###############################################################
#  Generated by:      Cadence Innovus 23.12-s091_1
#  OS:                Linux x86_64(Host ID ecelinux-10.ece.cornell.edu)
#  Generated on:      Mon Oct 19 13:02:27 2026
#  Design:            mult
#  Command:           write_lef_abstract ./output/mult.0.8.lef -stripePin -cutObsMinSpacing -PGpinLayers {1 2 3 4 5 6 7 8 9} -specifyTopLayer 7
###############################################################

VERSION 5.8 ;

BUSBITCHARS "[]" ;
DIVIDERCHAR "/" ;

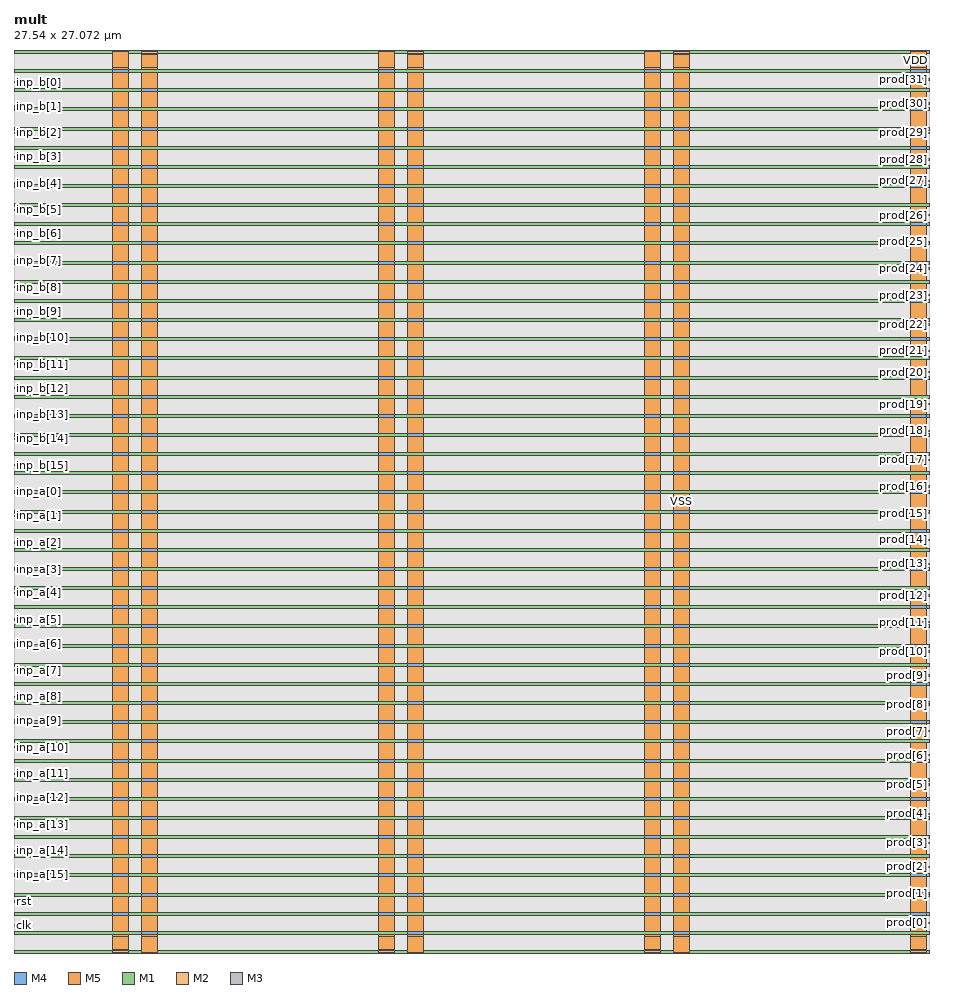
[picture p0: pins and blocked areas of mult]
MACRO mult
  CLASS BLOCK ;
  SIZE 27.540000 BY 27.072000 ;
  FOREIGN mult 0.000000 0.000000 ;
  ORIGIN 0 0 ;
  SYMMETRY X Y R90 ;
  PIN inp_a[15]
    DIRECTION INPUT ;
    USE SIGNAL ;
    ANTENNAPARTIALMETALAREA 0.0134 LAYER M4  ;
    ANTENNAPARTIALMETALSIDEAREA 0.000335 LAYER M4  ;
    ANTENNAPARTIALCUTAREA 0.0016 LAYER VIA4  ;
    ANTENNAPARTIALMETALAREA 0.5392 LAYER M5  ;
    ANTENNAPARTIALMETALSIDEAREA 0.01356 LAYER M5  ;
    ANTENNAMODEL OXIDE1 ;
    ANTENNAGATEAREA 0.007 LAYER M5  ;
    ANTENNAMAXAREACAR 150.658 LAYER M5  ;
    ANTENNAMAXSIDEAREACAR 4.14217 LAYER M5  ;
    ANTENNAMAXCUTCAR 4.32457 LAYER VIA5  ;
    PORT
      LAYER M4 ;
        RECT 0.000000 2.300000 0.375000 2.340000 ;
    END
  END inp_a[15]
  PIN inp_a[14]
    DIRECTION INPUT ;
    USE SIGNAL ;
    ANTENNAPARTIALMETALAREA 0.1702 LAYER M4  ;
    ANTENNAPARTIALMETALSIDEAREA 0.004255 LAYER M4  ;
    ANTENNAPARTIALCUTAREA 0.0016 LAYER VIA4  ;
    ANTENNAPARTIALMETALAREA 0.4824 LAYER M5  ;
    ANTENNAPARTIALMETALSIDEAREA 0.0121 LAYER M5  ;
    ANTENNAMODEL OXIDE1 ;
    ANTENNAGATEAREA 0.002 LAYER M5  ;
    ANTENNAMAXAREACAR 296.762 LAYER M5  ;
    ANTENNAMAXSIDEAREACAR 7.839 LAYER M5  ;
    ANTENNAMAXCUTCAR 3.872 LAYER VIA5  ;
    PORT
      LAYER M4 ;
        RECT 0.000000 3.020000 0.375000 3.060000 ;
    END
  END inp_a[14]
  PIN inp_a[13]
    DIRECTION INPUT ;
    USE SIGNAL ;
    ANTENNAPARTIALMETALAREA 0.0942 LAYER M4  ;
    ANTENNAPARTIALMETALSIDEAREA 0.002395 LAYER M4  ;
    ANTENNAMODEL OXIDE1 ;
    ANTENNAGATEAREA 0.008 LAYER M4  ;
    ANTENNAMAXAREACAR 109.725 LAYER M4  ;
    ANTENNAMAXSIDEAREACAR 3.3195 LAYER M4  ;
    ANTENNAMAXCUTCAR 4.224 LAYER VIA4  ;
    PORT
      LAYER M4 ;
        RECT 0.000000 3.820000 0.375000 3.860000 ;
    END
  END inp_a[13]
  PIN inp_a[12]
    DIRECTION INPUT ;
    USE SIGNAL ;
    ANTENNAMODEL OXIDE1 ;
    ANTENNAGATEAREA 0.002 LAYER M4  ;
    ANTENNAMAXAREACAR 88.106 LAYER M4  ;
    ANTENNAMAXSIDEAREACAR 2.8045 LAYER M4  ;
    ANTENNAMAXCUTCAR 2.048 LAYER VIA4  ;
    PORT
      LAYER M4 ;
        RECT 0.000000 4.620000 0.375000 4.660000 ;
    END
  END inp_a[12]
  PIN inp_a[11]
    DIRECTION INPUT ;
    USE SIGNAL ;
    ANTENNAPARTIALMETALAREA 0.07884 LAYER M4  ;
    ANTENNAPARTIALMETALSIDEAREA 0.002011 LAYER M4  ;
    ANTENNAMODEL OXIDE1 ;
    ANTENNAGATEAREA 0.008 LAYER M4  ;
    ANTENNAMAXAREACAR 108.321 LAYER M4  ;
    ANTENNAMAXSIDEAREACAR 3.28763 LAYER M4  ;
    ANTENNAMAXCUTCAR 4.224 LAYER VIA4  ;
    PORT
      LAYER M4 ;
        RECT 0.000000 5.340000 0.375000 5.380000 ;
    END
  END inp_a[11]
  PIN inp_a[10]
    DIRECTION INPUT ;
    USE SIGNAL ;
    ANTENNAMODEL OXIDE1 ;
    ANTENNAGATEAREA 0.002 LAYER M4  ;
    ANTENNAMAXAREACAR 158.442 LAYER M4  ;
    ANTENNAMAXSIDEAREACAR 5.0345 LAYER M4  ;
    ANTENNAMAXCUTCAR 3.584 LAYER VIA4  ;
    PORT
      LAYER M4 ;
        RECT 0.000000 6.140000 0.375000 6.180000 ;
    END
  END inp_a[10]
  PIN inp_a[9]
    DIRECTION INPUT ;
    USE SIGNAL ;
    ANTENNAPARTIALMETALAREA 0.04044 LAYER M4  ;
    ANTENNAPARTIALMETALSIDEAREA 0.001051 LAYER M4  ;
    ANTENNAMODEL OXIDE1 ;
    ANTENNAGATEAREA 0.002 LAYER M4  ;
    ANTENNAMAXAREACAR 64.502 LAYER M4  ;
    ANTENNAMAXSIDEAREACAR 1.8765 LAYER M4  ;
    ANTENNAMAXCUTCAR 3.584 LAYER VIA4  ;
    PORT
      LAYER M4 ;
        RECT 0.000000 6.940000 0.375000 6.980000 ;
    END
  END inp_a[9]
  PIN inp_a[8]
    DIRECTION INPUT ;
    USE SIGNAL ;
    ANTENNAPARTIALMETALAREA 0.2374 LAYER M4  ;
    ANTENNAPARTIALMETALSIDEAREA 0.005935 LAYER M4  ;
    ANTENNAPARTIALCUTAREA 0.0016 LAYER VIA4  ;
    ANTENNAPARTIALMETALAREA 0.1528 LAYER M5  ;
    ANTENNAPARTIALMETALSIDEAREA 0.00386 LAYER M5  ;
    ANTENNAMODEL OXIDE1 ;
    ANTENNAGATEAREA 0.002 LAYER M5  ;
    ANTENNAMAXAREACAR 173.886 LAYER M5  ;
    ANTENNAMAXSIDEAREACAR 4.9725 LAYER M5  ;
    ANTENNAMAXCUTCAR 3.36 LAYER VIA5  ;
    PORT
      LAYER M4 ;
        RECT 0.000000 7.660000 0.375000 7.700000 ;
    END
  END inp_a[8]
  PIN inp_a[7]
    DIRECTION INPUT ;
    USE SIGNAL ;
    ANTENNAPARTIALMETALAREA 0.129 LAYER M4  ;
    ANTENNAPARTIALMETALSIDEAREA 0.003305 LAYER M4  ;
    ANTENNAMODEL OXIDE1 ;
    ANTENNAGATEAREA 0.006 LAYER M4  ;
    ANTENNAMAXAREACAR 199.913 LAYER M4  ;
    ANTENNAMAXSIDEAREACAR 6.09663 LAYER M4  ;
    ANTENNAMAXCUTCAR 5.12 LAYER VIA4  ;
    PORT
      LAYER M4 ;
        RECT 0.000000 8.460000 0.375000 8.500000 ;
    END
  END inp_a[7]
  PIN inp_a[6]
    DIRECTION INPUT ;
    USE SIGNAL ;
    ANTENNAPARTIALMETALAREA 0.04336 LAYER M4  ;
    ANTENNAPARTIALMETALSIDEAREA 0.001084 LAYER M4  ;
    ANTENNAMODEL OXIDE1 ;
    ANTENNAGATEAREA 0.002 LAYER M4  ;
    ANTENNAMAXAREACAR 65.226 LAYER M4  ;
    ANTENNAMAXSIDEAREACAR 1.97 LAYER M4  ;
    ANTENNAMAXCUTCAR 2.56 LAYER VIA4  ;
    PORT
      LAYER M4 ;
        RECT 0.000000 9.260000 0.375000 9.300000 ;
    END
  END inp_a[6]
  PIN inp_a[5]
    DIRECTION INPUT ;
    USE SIGNAL ;
    ANTENNAPARTIALMETALAREA 0.04044 LAYER M4  ;
    ANTENNAPARTIALMETALSIDEAREA 0.001051 LAYER M4  ;
    ANTENNAMODEL OXIDE1 ;
    ANTENNAGATEAREA 0.003 LAYER M4  ;
    ANTENNAMAXAREACAR 65.8847 LAYER M4  ;
    ANTENNAMAXSIDEAREACAR 1.93383 LAYER M4  ;
    ANTENNAMAXCUTCAR 3.41333 LAYER VIA4  ;
    PORT
      LAYER M4 ;
        RECT 0.000000 9.980000 0.375000 10.020000 ;
    END
  END inp_a[5]
  PIN inp_a[4]
    DIRECTION INPUT ;
    USE SIGNAL ;
    ANTENNAPARTIALMETALAREA 0.04336 LAYER M4  ;
    ANTENNAPARTIALMETALSIDEAREA 0.001084 LAYER M4  ;
    ANTENNAMODEL OXIDE1 ;
    ANTENNAGATEAREA 0.002 LAYER M4  ;
    ANTENNAMAXAREACAR 65.226 LAYER M4  ;
    ANTENNAMAXSIDEAREACAR 1.97 LAYER M4  ;
    ANTENNAMAXCUTCAR 2.56 LAYER VIA4  ;
    PORT
      LAYER M4 ;
        RECT 0.000000 10.780000 0.375000 10.820000 ;
    END
  END inp_a[4]
  PIN inp_a[3]
    DIRECTION INPUT ;
    USE SIGNAL ;
    ANTENNAPARTIALMETALAREA 0.408 LAYER M4  ;
    ANTENNAPARTIALMETALSIDEAREA 0.01036 LAYER M4  ;
    ANTENNAMODEL OXIDE1 ;
    ANTENNAGATEAREA 0.003 LAYER M4  ;
    ANTENNAMAXAREACAR 210.362 LAYER M4  ;
    ANTENNAMAXSIDEAREACAR 5.79233 LAYER M4  ;
    ANTENNAPARTIALCUTAREA 0.0016 LAYER VIA4  ;
    ANTENNAMAXCUTCAR 6.67733 LAYER VIA4  ;
    ANTENNAPARTIALMETALAREA 0.0888 LAYER M5  ;
    ANTENNAPARTIALMETALSIDEAREA 0.00226 LAYER M5  ;
    ANTENNAGATEAREA 0.008 LAYER M5  ;
    ANTENNAMAXAREACAR 221.462 LAYER M5  ;
    ANTENNAMAXSIDEAREACAR 6.07483 LAYER M5  ;
    ANTENNAMAXCUTCAR 6.67733 LAYER VIA5  ;
    PORT
      LAYER M4 ;
        RECT 0.000000 11.500000 0.375000 11.540000 ;
    END
  END inp_a[3]
  PIN inp_a[2]
    DIRECTION INPUT ;
    USE SIGNAL ;
    ANTENNAPARTIALMETALAREA 0.13552 LAYER M4  ;
    ANTENNAPARTIALMETALSIDEAREA 0.003388 LAYER M4  ;
    ANTENNAMODEL OXIDE1 ;
    ANTENNAGATEAREA 0.002 LAYER M4  ;
    ANTENNAMAXAREACAR 124.314 LAYER M4  ;
    ANTENNAMAXSIDEAREACAR 3.5285 LAYER M4  ;
    ANTENNAMAXCUTCAR 2.56 LAYER VIA4  ;
    PORT
      LAYER M4 ;
        RECT 0.000000 12.300000 0.375000 12.340000 ;
    END
  END inp_a[2]
  PIN inp_a[1]
    DIRECTION INPUT ;
    USE SIGNAL ;
    ANTENNAPARTIALMETALAREA 0.21732 LAYER M4  ;
    ANTENNAPARTIALMETALSIDEAREA 0.005433 LAYER M4  ;
    ANTENNAMODEL OXIDE1 ;
    ANTENNAGATEAREA 0.007 LAYER M4  ;
    ANTENNAMAXAREACAR 113.696 LAYER M4  ;
    ANTENNAMAXSIDEAREACAR 3.32614 LAYER M4  ;
    ANTENNAMAXCUTCAR 4.43733 LAYER VIA4  ;
    PORT
      LAYER M4 ;
        RECT 0.000000 13.100000 0.375000 13.140000 ;
    END
  END inp_a[1]
  PIN inp_a[0]
    DIRECTION INPUT ;
    USE SIGNAL ;
    ANTENNAMODEL OXIDE1 ;
    ANTENNAGATEAREA 0.001 LAYER M4  ;
    ANTENNAMAXAREACAR 70.952 LAYER M4  ;
    ANTENNAMAXSIDEAREACAR 2.21 LAYER M4  ;
    ANTENNAMAXCUTCAR 3.072 LAYER VIA4  ;
    PORT
      LAYER M4 ;
        RECT 0.000000 13.820000 0.375000 13.860000 ;
    END
  END inp_a[0]
  PIN inp_b[15]
    DIRECTION INPUT ;
    USE SIGNAL ;
    ANTENNAPARTIALMETALAREA 0.59272 LAYER M4  ;
    ANTENNAPARTIALMETALSIDEAREA 0.014858 LAYER M4  ;
    ANTENNAMODEL OXIDE1 ;
    ANTENNAGATEAREA 0.005 LAYER M4  ;
    ANTENNAMAXAREACAR 309.418 LAYER M4  ;
    ANTENNAMAXSIDEAREACAR 8.9876 LAYER M4  ;
    ANTENNAPARTIALCUTAREA 0.0016 LAYER VIA4  ;
    ANTENNAMAXCUTCAR 3.392 LAYER VIA4  ;
    ANTENNAPARTIALMETALAREA 0.3504 LAYER M5  ;
    ANTENNAPARTIALMETALSIDEAREA 0.00884 LAYER M5  ;
    ANTENNAGATEAREA 0.009 LAYER M5  ;
    ANTENNAMAXAREACAR 348.351 LAYER M5  ;
    ANTENNAMAXSIDEAREACAR 9.96982 LAYER M5  ;
    ANTENNAMAXCUTCAR 5.92 LAYER VIA5  ;
    PORT
      LAYER M4 ;
        RECT 0.000000 14.620000 0.375000 14.660000 ;
    END
  END inp_b[15]
  PIN inp_b[14]
    DIRECTION INPUT ;
    USE SIGNAL ;
    ANTENNAPARTIALMETALAREA 0.55328 LAYER M4  ;
    ANTENNAPARTIALMETALSIDEAREA 0.013752 LAYER M4  ;
    ANTENNAMODEL OXIDE1 ;
    ANTENNAGATEAREA 0.009 LAYER M4  ;
    ANTENNAMAXAREACAR 257.342 LAYER M4  ;
    ANTENNAMAXSIDEAREACAR 7.732 LAYER M4  ;
    ANTENNAMAXCUTCAR 5.12 LAYER VIA4  ;
    PORT
      LAYER M4 ;
        RECT 0.000000 15.420000 0.375000 15.460000 ;
    END
  END inp_b[14]
  PIN inp_b[13]
    DIRECTION INPUT ;
    USE SIGNAL ;
    ANTENNAPARTIALMETALAREA 0.0838 LAYER M4  ;
    ANTENNAPARTIALMETALSIDEAREA 0.002095 LAYER M4  ;
    ANTENNAPARTIALCUTAREA 0.0016 LAYER VIA4  ;
    ANTENNAPARTIALMETALAREA 0.3576 LAYER M5  ;
    ANTENNAPARTIALMETALSIDEAREA 0.00898 LAYER M5  ;
    ANTENNAMODEL OXIDE1 ;
    ANTENNAGATEAREA 0.009 LAYER M5  ;
    ANTENNAMAXAREACAR 347.721 LAYER M5  ;
    ANTENNAMAXSIDEAREACAR 10.034 LAYER M5  ;
    ANTENNAMAXCUTCAR 5.44 LAYER VIA5  ;
    PORT
      LAYER M4 ;
        RECT 0.000000 16.140000 0.375000 16.180000 ;
    END
  END inp_b[13]
  PIN inp_b[12]
    DIRECTION INPUT ;
    USE SIGNAL ;
    ANTENNAPARTIALMETALAREA 0.76368 LAYER M4  ;
    ANTENNAPARTIALMETALSIDEAREA 0.019252 LAYER M4  ;
    ANTENNAMODEL OXIDE1 ;
    ANTENNAGATEAREA 0.006 LAYER M4  ;
    ANTENNAMAXAREACAR 241.898 LAYER M4  ;
    ANTENNAMAXSIDEAREACAR 6.87367 LAYER M4  ;
    ANTENNAPARTIALCUTAREA 0.0016 LAYER VIA4  ;
    ANTENNAMAXCUTCAR 5.38667 LAYER VIA4  ;
    ANTENNAPARTIALMETALAREA 0.252 LAYER M5  ;
    ANTENNAPARTIALMETALSIDEAREA 0.00634 LAYER M5  ;
    ANTENNAGATEAREA 0.009 LAYER M5  ;
    ANTENNAMAXAREACAR 269.898 LAYER M5  ;
    ANTENNAMAXSIDEAREACAR 7.57811 LAYER M5  ;
    ANTENNAMAXCUTCAR 5.38667 LAYER VIA5  ;
    PORT
      LAYER M4 ;
        RECT 0.000000 16.940000 0.375000 16.980000 ;
    END
  END inp_b[12]
  PIN inp_b[11]
    DIRECTION INPUT ;
    USE SIGNAL ;
    ANTENNAPARTIALMETALAREA 0.231 LAYER M4  ;
    ANTENNAPARTIALMETALSIDEAREA 0.005695 LAYER M4  ;
    ANTENNAMODEL OXIDE1 ;
    ANTENNAGATEAREA 0.001 LAYER M4  ;
    ANTENNAMAXAREACAR 309.778 LAYER M4  ;
    ANTENNAMAXSIDEAREACAR 8.24 LAYER M4  ;
    ANTENNAPARTIALCUTAREA 0.0032 LAYER VIA4  ;
    ANTENNAMAXCUTCAR 6.272 LAYER VIA4  ;
    ANTENNAPARTIALMETALAREA 0.484 LAYER M5  ;
    ANTENNAPARTIALMETALSIDEAREA 0.01222 LAYER M5  ;
    ANTENNAGATEAREA 0.009 LAYER M5  ;
    ANTENNAMAXAREACAR 363.556 LAYER M5  ;
    ANTENNAMAXSIDEAREACAR 9.59778 LAYER M5  ;
    ANTENNAMAXCUTCAR 6.272 LAYER VIA5  ;
    PORT
      LAYER M4 ;
        RECT 0.000000 17.660000 0.375000 17.700000 ;
    END
  END inp_b[11]
  PIN inp_b[10]
    DIRECTION INPUT ;
    USE SIGNAL ;
    ANTENNAPARTIALMETALAREA 0.37392 LAYER M4  ;
    ANTENNAPARTIALMETALSIDEAREA 0.009468 LAYER M4  ;
    ANTENNAMODEL OXIDE1 ;
    ANTENNAGATEAREA 0.006 LAYER M4  ;
    ANTENNAMAXAREACAR 272.842 LAYER M4  ;
    ANTENNAMAXSIDEAREACAR 8.24 LAYER M4  ;
    ANTENNAPARTIALCUTAREA 0.0032 LAYER VIA4  ;
    ANTENNAMAXCUTCAR 5.65333 LAYER VIA4  ;
    ANTENNAPARTIALMETALAREA 0.2736 LAYER M5  ;
    ANTENNAPARTIALMETALSIDEAREA 0.00692 LAYER M5  ;
    ANTENNAGATEAREA 0.009 LAYER M5  ;
    ANTENNAMAXAREACAR 303.242 LAYER M5  ;
    ANTENNAMAXSIDEAREACAR 9.00889 LAYER M5  ;
    ANTENNAMAXCUTCAR 5.65333 LAYER VIA5  ;
    PORT
      LAYER M4 ;
        RECT 0.000000 18.460000 0.375000 18.500000 ;
    END
  END inp_b[10]
  PIN inp_b[9]
    DIRECTION INPUT ;
    USE SIGNAL ;
    ANTENNAPARTIALMETALAREA 0.27936 LAYER M4  ;
    ANTENNAPARTIALMETALSIDEAREA 0.007064 LAYER M4  ;
    ANTENNAMODEL OXIDE1 ;
    ANTENNAGATEAREA 0.006 LAYER M4  ;
    ANTENNAMAXAREACAR 229.775 LAYER M4  ;
    ANTENNAMAXSIDEAREACAR 6.97533 LAYER M4  ;
    ANTENNAPARTIALCUTAREA 0.0016 LAYER VIA4  ;
    ANTENNAMAXCUTCAR 5.38667 LAYER VIA4  ;
    ANTENNAPARTIALMETALAREA 0.4536 LAYER M5  ;
    ANTENNAPARTIALMETALSIDEAREA 0.01138 LAYER M5  ;
    ANTENNAGATEAREA 0.009 LAYER M5  ;
    ANTENNAMAXAREACAR 280.175 LAYER M5  ;
    ANTENNAMAXSIDEAREACAR 8.23978 LAYER M5  ;
    ANTENNAMAXCUTCAR 5.38667 LAYER VIA5  ;
    PORT
      LAYER M4 ;
        RECT 0.000000 19.260000 0.375000 19.300000 ;
    END
  END inp_b[9]
  PIN inp_b[8]
    DIRECTION INPUT ;
    USE SIGNAL ;
    ANTENNAPARTIALMETALAREA 0.26912 LAYER M4  ;
    ANTENNAPARTIALMETALSIDEAREA 0.006808 LAYER M4  ;
    ANTENNAMODEL OXIDE1 ;
    ANTENNAGATEAREA 0.009 LAYER M4  ;
    ANTENNAMAXAREACAR 154.056 LAYER M4  ;
    ANTENNAMAXSIDEAREACAR 4.68516 LAYER M4  ;
    ANTENNAMAXCUTCAR 4.096 LAYER VIA4  ;
    PORT
      LAYER M4 ;
        RECT 0.000000 19.980000 0.375000 20.020000 ;
    END
  END inp_b[8]
  PIN inp_b[7]
    DIRECTION INPUT ;
    USE SIGNAL ;
    ANTENNAPARTIALMETALAREA 0.5384 LAYER M4  ;
    ANTENNAPARTIALMETALSIDEAREA 0.01362 LAYER M4  ;
    ANTENNAMODEL OXIDE1 ;
    ANTENNAGATEAREA 0.009 LAYER M4  ;
    ANTENNAMAXAREACAR 277.36 LAYER M4  ;
    ANTENNAMAXSIDEAREACAR 8.37858 LAYER M4  ;
    ANTENNAMAXCUTCAR 4.096 LAYER VIA4  ;
    PORT
      LAYER M4 ;
        RECT 0.000000 20.780000 0.375000 20.820000 ;
    END
  END inp_b[7]
  PIN inp_b[6]
    DIRECTION INPUT ;
    USE SIGNAL ;
    ANTENNAPARTIALMETALAREA 0.0774 LAYER M4  ;
    ANTENNAPARTIALMETALSIDEAREA 0.001935 LAYER M4  ;
    ANTENNAPARTIALCUTAREA 0.0016 LAYER VIA4  ;
    ANTENNAPARTIALMETALAREA 0.22 LAYER M5  ;
    ANTENNAPARTIALMETALSIDEAREA 0.00554 LAYER M5  ;
    ANTENNAMODEL OXIDE1 ;
    ANTENNAGATEAREA 0.009 LAYER M5  ;
    ANTENNAMAXAREACAR 489.58 LAYER M5  ;
    ANTENNAMAXSIDEAREACAR 12.8336 LAYER M5  ;
    ANTENNAMAXCUTCAR 5.32 LAYER VIA5  ;
    PORT
      LAYER M4 ;
        RECT 0.000000 21.580000 0.375000 21.620000 ;
    END
  END inp_b[6]
  PIN inp_b[5]
    DIRECTION INPUT ;
    USE SIGNAL ;
    ANTENNAPARTIALMETALAREA 0.1766 LAYER M4  ;
    ANTENNAPARTIALMETALSIDEAREA 0.004335 LAYER M4  ;
    ANTENNAPARTIALCUTAREA 0.0016 LAYER VIA4  ;
    ANTENNAPARTIALMETALAREA 0.6352 LAYER M5  ;
    ANTENNAPARTIALMETALSIDEAREA 0.01596 LAYER M5  ;
    ANTENNAMODEL OXIDE1 ;
    ANTENNAGATEAREA 0.009 LAYER M5  ;
    ANTENNAMAXAREACAR 285.236 LAYER M5  ;
    ANTENNAMAXSIDEAREACAR 8.206 LAYER M5  ;
    ANTENNAMAXCUTCAR 4.896 LAYER VIA5  ;
    PORT
      LAYER M4 ;
        RECT 0.000000 22.300000 0.375000 22.340000 ;
    END
  END inp_b[5]
  PIN inp_b[4]
    DIRECTION INPUT ;
    USE SIGNAL ;
    ANTENNAPARTIALMETALAREA 0.62288 LAYER M4  ;
    ANTENNAPARTIALMETALSIDEAREA 0.015732 LAYER M4  ;
    ANTENNAMODEL OXIDE1 ;
    ANTENNAGATEAREA 0.009 LAYER M4  ;
    ANTENNAMAXAREACAR 266.611 LAYER M4  ;
    ANTENNAMAXSIDEAREACAR 8 LAYER M4  ;
    ANTENNAMAXCUTCAR 5.12 LAYER VIA4  ;
    PORT
      LAYER M4 ;
        RECT 0.000000 23.100000 0.375000 23.140000 ;
    END
  END inp_b[4]
  PIN inp_b[3]
    DIRECTION INPUT ;
    USE SIGNAL ;
    ANTENNAPARTIALMETALAREA 0.78364 LAYER M4  ;
    ANTENNAPARTIALMETALSIDEAREA 0.019671 LAYER M4  ;
    ANTENNAMODEL OXIDE1 ;
    ANTENNAGATEAREA 0.005 LAYER M4  ;
    ANTENNAMAXAREACAR 640.658 LAYER M4  ;
    ANTENNAMAXSIDEAREACAR 19.2042 LAYER M4  ;
    ANTENNAPARTIALCUTAREA 0.0016 LAYER VIA4  ;
    ANTENNAMAXCUTCAR 8.512 LAYER VIA4  ;
    ANTENNAPARTIALMETALAREA 0.0312 LAYER M5  ;
    ANTENNAPARTIALMETALSIDEAREA 0.00082 LAYER M5  ;
    ANTENNAGATEAREA 0.009 LAYER M5  ;
    ANTENNAMAXAREACAR 644.125 LAYER M5  ;
    ANTENNAMAXSIDEAREACAR 19.2953 LAYER M5  ;
    ANTENNAMAXCUTCAR 8.512 LAYER VIA5  ;
    PORT
      LAYER M4 ;
        RECT 0.000000 23.900000 0.375000 23.940000 ;
    END
  END inp_b[3]
  PIN inp_b[2]
    DIRECTION INPUT ;
    USE SIGNAL ;
    ANTENNAPARTIALMETALAREA 0.2246 LAYER M4  ;
    ANTENNAPARTIALMETALSIDEAREA 0.005535 LAYER M4  ;
    ANTENNAPARTIALCUTAREA 0.0016 LAYER VIA4  ;
    ANTENNAPARTIALMETALAREA 0.7536 LAYER M5  ;
    ANTENNAPARTIALMETALSIDEAREA 0.01892 LAYER M5  ;
    ANTENNAMODEL OXIDE1 ;
    ANTENNAGATEAREA 0.009 LAYER M5  ;
    ANTENNAMAXAREACAR 278.262 LAYER M5  ;
    ANTENNAMAXSIDEAREACAR 7.92526 LAYER M5  ;
    ANTENNAMAXCUTCAR 7.296 LAYER VIA5  ;
    PORT
      LAYER M4 ;
        RECT 0.000000 24.620000 0.375000 24.660000 ;
    END
  END inp_b[2]
  PIN inp_b[1]
    DIRECTION INPUT ;
    USE SIGNAL ;
    ANTENNAPARTIALMETALAREA 0.80952 LAYER M4  ;
    ANTENNAPARTIALMETALSIDEAREA 0.020278 LAYER M4  ;
    ANTENNAMODEL OXIDE1 ;
    ANTENNAGATEAREA 0.009 LAYER M4  ;
    ANTENNAMAXAREACAR 524.565 LAYER M4  ;
    ANTENNAMAXSIDEAREACAR 15.9181 LAYER M4  ;
    ANTENNAMAXCUTCAR 5.12 LAYER VIA4  ;
    PORT
      LAYER M4 ;
        RECT 0.000000 25.420000 0.375000 25.460000 ;
    END
  END inp_b[1]
  PIN inp_b[0]
    DIRECTION INPUT ;
    USE SIGNAL ;
    ANTENNAPARTIALMETALAREA 0.41416 LAYER M4  ;
    ANTENNAPARTIALMETALSIDEAREA 0.010314 LAYER M4  ;
    ANTENNAMODEL OXIDE1 ;
    ANTENNAGATEAREA 0.01 LAYER M4  ;
    ANTENNAMAXAREACAR 256.591 LAYER M4  ;
    ANTENNAMAXSIDEAREACAR 7.7519 LAYER M4  ;
    ANTENNAMAXCUTCAR 3.41333 LAYER VIA4  ;
    PORT
      LAYER M4 ;
        RECT 0.000000 26.140000 0.375000 26.180000 ;
    END
  END inp_b[0]
  PIN prod[31]
    DIRECTION OUTPUT ;
    USE SIGNAL ;
    ANTENNADIFFAREA 0.001 LAYER M4  ;
    ANTENNAPARTIALMETALAREA 0.07744 LAYER M4  ;
    ANTENNAPARTIALMETALSIDEAREA 0.001936 LAYER M4  ;
    PORT
      LAYER M4 ;
        RECT 27.165000 26.220000 27.540000 26.260000 ;
    END
  END prod[31]
  PIN prod[30]
    DIRECTION OUTPUT ;
    USE SIGNAL ;
    ANTENNADIFFAREA 0.001 LAYER M4  ;
    ANTENNAPARTIALMETALAREA 0.01344 LAYER M4  ;
    ANTENNAPARTIALMETALSIDEAREA 0.000336 LAYER M4  ;
    PORT
      LAYER M4 ;
        RECT 27.165000 25.500000 27.540000 25.540000 ;
    END
  END prod[30]
  PIN prod[29]
    DIRECTION OUTPUT ;
    USE SIGNAL ;
    ANTENNADIFFAREA 0.001 LAYER M4  ;
    ANTENNAPARTIALMETALAREA 0.07744 LAYER M4  ;
    ANTENNAPARTIALMETALSIDEAREA 0.001936 LAYER M4  ;
    PORT
      LAYER M4 ;
        RECT 27.165000 24.620000 27.540000 24.660000 ;
    END
  END prod[29]
  PIN prod[28]
    DIRECTION OUTPUT ;
    USE SIGNAL ;
    ANTENNADIFFAREA 0.001 LAYER M4  ;
    PORT
      LAYER M4 ;
        RECT 27.165000 23.820000 27.540000 23.860000 ;
    END
  END prod[28]
  PIN prod[27]
    DIRECTION OUTPUT ;
    USE SIGNAL ;
    ANTENNADIFFAREA 0.001 LAYER M4  ;
    ANTENNAPARTIALMETALAREA 0.01344 LAYER M4  ;
    ANTENNAPARTIALMETALSIDEAREA 0.000336 LAYER M4  ;
    PORT
      LAYER M4 ;
        RECT 27.165000 23.180000 27.540000 23.220000 ;
    END
  END prod[27]
  PIN prod[26]
    DIRECTION OUTPUT ;
    USE SIGNAL ;
    ANTENNADIFFAREA 0.001 LAYER M4  ;
    ANTENNAPARTIALMETALAREA 0.01344 LAYER M4  ;
    ANTENNAPARTIALMETALSIDEAREA 0.000336 LAYER M4  ;
    PORT
      LAYER M4 ;
        RECT 27.165000 22.140000 27.540000 22.180000 ;
    END
  END prod[26]
  PIN prod[25]
    DIRECTION OUTPUT ;
    USE SIGNAL ;
    ANTENNADIFFAREA 0.001 LAYER M4  ;
    ANTENNAPARTIALMETALAREA 0.07744 LAYER M4  ;
    ANTENNAPARTIALMETALSIDEAREA 0.001936 LAYER M4  ;
    PORT
      LAYER M4 ;
        RECT 27.165000 21.340000 27.540000 21.380000 ;
    END
  END prod[25]
  PIN prod[24]
    DIRECTION OUTPUT ;
    USE SIGNAL ;
    ANTENNADIFFAREA 0.001 LAYER M4  ;
    ANTENNAPARTIALMETALAREA 0.01344 LAYER M4  ;
    ANTENNAPARTIALMETALSIDEAREA 0.000336 LAYER M4  ;
    PORT
      LAYER M4 ;
        RECT 27.165000 20.540000 27.540000 20.580000 ;
    END
  END prod[24]
  PIN prod[23]
    DIRECTION OUTPUT ;
    USE SIGNAL ;
    ANTENNADIFFAREA 0.001 LAYER M4  ;
    ANTENNAPARTIALMETALAREA 0.08 LAYER M4  ;
    ANTENNAPARTIALMETALSIDEAREA 0.002 LAYER M4  ;
    PORT
      LAYER M4 ;
        RECT 27.165000 19.740000 27.540000 19.780000 ;
    END
  END prod[23]
  PIN prod[22]
    DIRECTION OUTPUT ;
    USE SIGNAL ;
    ANTENNADIFFAREA 0.001 LAYER M4  ;
    ANTENNAPARTIALMETALAREA 0.07488 LAYER M4  ;
    ANTENNAPARTIALMETALSIDEAREA 0.001872 LAYER M4  ;
    PORT
      LAYER M4 ;
        RECT 27.165000 18.860000 27.540000 18.900000 ;
    END
  END prod[22]
  PIN prod[21]
    DIRECTION OUTPUT ;
    USE SIGNAL ;
    ANTENNADIFFAREA 0.001 LAYER M4  ;
    ANTENNAPARTIALMETALAREA 0.07488 LAYER M4  ;
    ANTENNAPARTIALMETALSIDEAREA 0.001872 LAYER M4  ;
    PORT
      LAYER M4 ;
        RECT 27.165000 18.060000 27.540000 18.100000 ;
    END
  END prod[21]
  PIN prod[20]
    DIRECTION OUTPUT ;
    USE SIGNAL ;
    ANTENNADIFFAREA 0.001 LAYER M4  ;
    ANTENNAPARTIALMETALAREA 0.08 LAYER M4  ;
    ANTENNAPARTIALMETALSIDEAREA 0.002 LAYER M4  ;
    PORT
      LAYER M4 ;
        RECT 27.165000 17.420000 27.540000 17.460000 ;
    END
  END prod[20]
  PIN prod[19]
    DIRECTION OUTPUT ;
    USE SIGNAL ;
    ANTENNADIFFAREA 0.001 LAYER M4  ;
    ANTENNAPARTIALMETALAREA 0.01344 LAYER M4  ;
    ANTENNAPARTIALMETALSIDEAREA 0.000336 LAYER M4  ;
    PORT
      LAYER M4 ;
        RECT 27.165000 16.460000 27.540000 16.500000 ;
    END
  END prod[19]
  PIN prod[18]
    DIRECTION OUTPUT ;
    USE SIGNAL ;
    ANTENNADIFFAREA 0.001 LAYER M4  ;
    ANTENNAPARTIALMETALAREA 0.07744 LAYER M4  ;
    ANTENNAPARTIALMETALSIDEAREA 0.001936 LAYER M4  ;
    PORT
      LAYER M4 ;
        RECT 27.165000 15.660000 27.540000 15.700000 ;
    END
  END prod[18]
  PIN prod[17]
    DIRECTION OUTPUT ;
    USE SIGNAL ;
    ANTENNADIFFAREA 0.001 LAYER M4  ;
    PORT
      LAYER M4 ;
        RECT 27.165000 14.780000 27.540000 14.820000 ;
    END
  END prod[17]
  PIN prod[16]
    DIRECTION OUTPUT ;
    USE SIGNAL ;
    ANTENNADIFFAREA 0.001 LAYER M4  ;
    ANTENNAPARTIALMETALAREA 0.03532 LAYER M4  ;
    ANTENNAPARTIALMETALSIDEAREA 0.000923 LAYER M4  ;
    PORT
      LAYER M4 ;
        RECT 27.165000 13.980000 27.540000 14.020000 ;
    END
  END prod[16]
  PIN prod[15]
    DIRECTION OUTPUT ;
    USE SIGNAL ;
    ANTENNADIFFAREA 0.001 LAYER M4  ;
    ANTENNAPARTIALMETALAREA 0.07884 LAYER M4  ;
    ANTENNAPARTIALMETALSIDEAREA 0.002011 LAYER M4  ;
    PORT
      LAYER M4 ;
        RECT 27.165000 13.180000 27.540000 13.220000 ;
    END
  END prod[15]
  PIN prod[14]
    DIRECTION OUTPUT ;
    USE SIGNAL ;
    ANTENNADIFFAREA 0.001 LAYER M4  ;
    ANTENNAPARTIALMETALAREA 0.00408 LAYER M4  ;
    ANTENNAPARTIALMETALSIDEAREA 0.000142 LAYER M4  ;
    PORT
      LAYER M4 ;
        RECT 27.165000 12.380000 27.540000 12.420000 ;
    END
  END prod[14]
  PIN prod[13]
    DIRECTION OUTPUT ;
    USE SIGNAL ;
    ANTENNADIFFAREA 0.001 LAYER M4  ;
    ANTENNAPARTIALMETALAREA 0.0174 LAYER M4  ;
    ANTENNAPARTIALMETALSIDEAREA 0.000475 LAYER M4  ;
    PORT
      LAYER M4 ;
        RECT 27.165000 11.660000 27.540000 11.700000 ;
    END
  END prod[13]
  PIN prod[12]
    DIRECTION OUTPUT ;
    USE SIGNAL ;
    ANTENNADIFFAREA 0.001 LAYER M4  ;
    ANTENNAPARTIALMETALAREA 0.07628 LAYER M4  ;
    ANTENNAPARTIALMETALSIDEAREA 0.001947 LAYER M4  ;
    PORT
      LAYER M4 ;
        RECT 27.165000 10.700000 27.540000 10.740000 ;
    END
  END prod[12]
  PIN prod[11]
    DIRECTION OUTPUT ;
    USE SIGNAL ;
    ANTENNADIFFAREA 0.001 LAYER M4  ;
    ANTENNAPARTIALMETALAREA 0.06092 LAYER M4  ;
    ANTENNAPARTIALMETALSIDEAREA 0.001563 LAYER M4  ;
    PORT
      LAYER M4 ;
        RECT 27.165000 9.900000 27.540000 9.940000 ;
    END
  END prod[11]
  PIN prod[10]
    DIRECTION OUTPUT ;
    USE SIGNAL ;
    ANTENNADIFFAREA 0.001 LAYER M4  ;
    ANTENNAPARTIALMETALAREA 0.03532 LAYER M4  ;
    ANTENNAPARTIALMETALSIDEAREA 0.000923 LAYER M4  ;
    PORT
      LAYER M4 ;
        RECT 27.165000 9.020000 27.540000 9.060000 ;
    END
  END prod[10]
  PIN prod[9]
    DIRECTION OUTPUT ;
    USE SIGNAL ;
    ANTENNADIFFAREA 0.001 LAYER M4  ;
    ANTENNAPARTIALMETALAREA 0.03532 LAYER M4  ;
    ANTENNAPARTIALMETALSIDEAREA 0.000923 LAYER M4  ;
    PORT
      LAYER M4 ;
        RECT 27.165000 8.300000 27.540000 8.340000 ;
    END
  END prod[9]
  PIN prod[8]
    DIRECTION OUTPUT ;
    USE SIGNAL ;
    ANTENNADIFFAREA 0.001 LAYER M4  ;
    ANTENNAPARTIALMETALAREA 0.00408 LAYER M4  ;
    ANTENNAPARTIALMETALSIDEAREA 0.000142 LAYER M4  ;
    PORT
      LAYER M4 ;
        RECT 27.165000 7.420000 27.540000 7.460000 ;
    END
  END prod[8]
  PIN prod[7]
    DIRECTION OUTPUT ;
    USE SIGNAL ;
    ANTENNADIFFAREA 0.001 LAYER M4  ;
    ANTENNAPARTIALMETALAREA 0.00408 LAYER M4  ;
    ANTENNAPARTIALMETALSIDEAREA 0.000142 LAYER M4  ;
    PORT
      LAYER M4 ;
        RECT 27.165000 6.620000 27.540000 6.660000 ;
    END
  END prod[7]
  PIN prod[6]
    DIRECTION OUTPUT ;
    USE SIGNAL ;
    ANTENNADIFFAREA 0.001 LAYER M4  ;
    ANTENNAPARTIALMETALAREA 0.03532 LAYER M4  ;
    ANTENNAPARTIALMETALSIDEAREA 0.000923 LAYER M4  ;
    PORT
      LAYER M4 ;
        RECT 27.165000 5.900000 27.540000 5.940000 ;
    END
  END prod[6]
  PIN prod[5]
    DIRECTION OUTPUT ;
    USE SIGNAL ;
    ANTENNADIFFAREA 0.001 LAYER M4  ;
    ANTENNAPARTIALMETALAREA 0.03532 LAYER M4  ;
    ANTENNAPARTIALMETALSIDEAREA 0.000923 LAYER M4  ;
    PORT
      LAYER M4 ;
        RECT 27.165000 5.020000 27.540000 5.060000 ;
    END
  END prod[5]
  PIN prod[4]
    DIRECTION OUTPUT ;
    USE SIGNAL ;
    ANTENNADIFFAREA 0.001 LAYER M4  ;
    ANTENNAPARTIALMETALAREA 0.03532 LAYER M4  ;
    ANTENNAPARTIALMETALSIDEAREA 0.000923 LAYER M4  ;
    PORT
      LAYER M4 ;
        RECT 27.165000 4.140000 27.540000 4.180000 ;
    END
  END prod[4]
  PIN prod[3]
    DIRECTION OUTPUT ;
    USE SIGNAL ;
    ANTENNADIFFAREA 0.001 LAYER M4  ;
    ANTENNAPARTIALMETALAREA 0.0174 LAYER M4  ;
    ANTENNAPARTIALMETALSIDEAREA 0.000475 LAYER M4  ;
    PORT
      LAYER M4 ;
        RECT 27.165000 3.260000 27.540000 3.300000 ;
    END
  END prod[3]
  PIN prod[2]
    DIRECTION OUTPUT ;
    USE SIGNAL ;
    ANTENNADIFFAREA 0.001 LAYER M4  ;
    ANTENNAPARTIALMETALAREA 0.04672 LAYER M4  ;
    ANTENNAPARTIALMETALSIDEAREA 0.001168 LAYER M4  ;
    PORT
      LAYER M4 ;
        RECT 27.165000 2.540000 27.540000 2.580000 ;
    END
  END prod[2]
  PIN prod[1]
    DIRECTION OUTPUT ;
    USE SIGNAL ;
    ANTENNADIFFAREA 0.001 LAYER M4  ;
    ANTENNAPARTIALMETALAREA 0.00408 LAYER M4  ;
    ANTENNAPARTIALMETALSIDEAREA 0.000142 LAYER M4  ;
    PORT
      LAYER M4 ;
        RECT 27.165000 1.740000 27.540000 1.780000 ;
    END
  END prod[1]
  PIN prod[0]
    DIRECTION OUTPUT ;
    USE SIGNAL ;
    ANTENNADIFFAREA 0.001 LAYER M4  ;
    ANTENNAPARTIALMETALAREA 0.01344 LAYER M4  ;
    ANTENNAPARTIALMETALSIDEAREA 0.000336 LAYER M4  ;
    PORT
      LAYER M4 ;
        RECT 27.165000 0.860000 27.540000 0.900000 ;
    END
  END prod[0]
  PIN clk
    DIRECTION INPUT ;
    USE SIGNAL ;
    ANTENNAPARTIALMETALAREA 0.0038 LAYER M4  ;
    ANTENNAPARTIALMETALSIDEAREA 9.5e-05 LAYER M4  ;
    ANTENNAPARTIALCUTAREA 0.0016 LAYER VIA4  ;
    ANTENNAPARTIALMETALAREA 0.076 LAYER M5  ;
    ANTENNAPARTIALMETALSIDEAREA 0.00194 LAYER M5  ;
    ANTENNAMODEL OXIDE1 ;
    ANTENNAGATEAREA 0.001 LAYER M5  ;
    ANTENNAMAXAREACAR 252.5 LAYER M5  ;
    ANTENNAMAXSIDEAREACAR 6.513 LAYER M5  ;
    ANTENNAMAXCUTCAR 4.672 LAYER VIA5  ;
    PORT
      LAYER M4 ;
        RECT 0.000000 0.780000 0.375000 0.820000 ;
    END
  END clk
  PIN rst
    DIRECTION INPUT ;
    USE SIGNAL ;
    ANTENNAPARTIALMETALAREA 0.29132 LAYER M4  ;
    ANTENNAPARTIALMETALSIDEAREA 0.007323 LAYER M4  ;
    ANTENNAMODEL OXIDE1 ;
    ANTENNAGATEAREA 0.001 LAYER M4  ;
    ANTENNAMAXAREACAR 325.784 LAYER M4  ;
    ANTENNAMAXSIDEAREACAR 8.364 LAYER M4  ;
    ANTENNAMAXCUTCAR 3.072 LAYER VIA4  ;
    PORT
      LAYER M4 ;
        RECT 0.000000 1.500000 0.375000 1.540000 ;
    END
  END rst
  PIN VDD
    DIRECTION INOUT ;
    USE POWER ;
    PORT
      LAYER M5 ;
        RECT 26.960000 0.000000 27.440000 27.072000 ;
    END
    PORT
      LAYER M5 ;
        RECT 18.960000 0.000000 19.440000 27.072000 ;
    END
    PORT
      LAYER M5 ;
        RECT 10.960000 0.000000 11.440000 27.072000 ;
    END
    PORT
      LAYER M5 ;
        RECT 2.960000 0.000000 3.440000 27.072000 ;
    END
    PORT
      LAYER M5 ;
        RECT 26.960000 26.592000 27.440000 27.072000 ;
    END
    PORT
      LAYER M5 ;
        RECT 26.960000 0.000000 27.440000 0.480000 ;
    END
    PORT
      LAYER M5 ;
        RECT 18.960000 26.592000 19.440000 27.072000 ;
    END
    PORT
      LAYER M5 ;
        RECT 18.960000 0.000000 19.440000 0.480000 ;
    END
    PORT
      LAYER M5 ;
        RECT 10.960000 26.592000 11.440000 27.072000 ;
    END
    PORT
      LAYER M5 ;
        RECT 10.960000 0.000000 11.440000 0.480000 ;
    END
    PORT
      LAYER M5 ;
        RECT 2.960000 26.592000 3.440000 27.072000 ;
    END
    PORT
      LAYER M5 ;
        RECT 2.960000 0.000000 3.440000 0.480000 ;
    END

# P/G power stripe data as pin
    PORT
      LAYER M1 ;
        RECT 0.000000 12.627000 27.540000 12.717000 ;
        RECT 0.000000 11.475000 27.540000 11.565000 ;
        RECT 0.000000 10.323000 27.540000 10.413000 ;
        RECT 0.000000 9.171000 27.540000 9.261000 ;
        RECT 0.000000 8.019000 27.540000 8.109000 ;
        RECT 0.000000 6.867000 27.540000 6.957000 ;
        RECT 0.000000 5.715000 27.540000 5.805000 ;
        RECT 0.000000 4.563000 27.540000 4.653000 ;
        RECT 0.000000 3.411000 27.540000 3.501000 ;
        RECT 0.000000 2.259000 27.540000 2.349000 ;
        RECT 0.000000 1.107000 27.540000 1.197000 ;
        RECT 0.000000 -0.045000 27.540000 0.045000 ;
        RECT 0.000000 26.451000 27.540000 26.541000 ;
        RECT 0.000000 25.299000 27.540000 25.389000 ;
        RECT 0.000000 24.147000 27.540000 24.237000 ;
        RECT 0.000000 22.995000 27.540000 23.085000 ;
        RECT 0.000000 21.843000 27.540000 21.933000 ;
        RECT 0.000000 20.691000 27.540000 20.781000 ;
        RECT 0.000000 19.539000 27.540000 19.629000 ;
        RECT 0.000000 18.387000 27.540000 18.477000 ;
        RECT 0.000000 17.235000 27.540000 17.325000 ;
        RECT 0.000000 16.083000 27.540000 16.173000 ;
        RECT 0.000000 14.931000 27.540000 15.021000 ;
        RECT 0.000000 13.779000 27.540000 13.869000 ;
      LAYER M2 ;
        RECT 2.960000 -0.005000 3.440000 0.045000 ;
        RECT 2.960000 1.107000 3.440000 1.197000 ;
        RECT 2.960000 2.259000 3.440000 2.349000 ;
        RECT 2.960000 3.411000 3.440000 3.501000 ;
        RECT 2.960000 4.563000 3.440000 4.653000 ;
        RECT 2.960000 5.715000 3.440000 5.805000 ;
        RECT 10.960000 -0.005000 11.440000 0.045000 ;
        RECT 10.960000 1.107000 11.440000 1.197000 ;
        RECT 10.960000 2.259000 11.440000 2.349000 ;
        RECT 10.960000 3.411000 11.440000 3.501000 ;
        RECT 10.960000 4.563000 11.440000 4.653000 ;
        RECT 10.960000 5.715000 11.440000 5.805000 ;
        RECT 2.960000 9.171000 3.440000 9.261000 ;
        RECT 2.960000 8.019000 3.440000 8.109000 ;
        RECT 2.960000 6.867000 3.440000 6.957000 ;
        RECT 2.960000 12.627000 3.440000 12.717000 ;
        RECT 2.960000 11.475000 3.440000 11.565000 ;
        RECT 2.960000 10.323000 3.440000 10.413000 ;
        RECT 10.960000 6.867000 11.440000 6.957000 ;
        RECT 10.960000 8.019000 11.440000 8.109000 ;
        RECT 10.960000 9.171000 11.440000 9.261000 ;
        RECT 10.960000 10.323000 11.440000 10.413000 ;
        RECT 10.960000 11.475000 11.440000 11.565000 ;
        RECT 10.960000 12.627000 11.440000 12.717000 ;
        RECT 18.960000 -0.005000 19.440000 0.045000 ;
        RECT 18.960000 1.107000 19.440000 1.197000 ;
        RECT 18.960000 2.259000 19.440000 2.349000 ;
        RECT 18.960000 3.411000 19.440000 3.501000 ;
        RECT 18.960000 4.563000 19.440000 4.653000 ;
        RECT 18.960000 5.715000 19.440000 5.805000 ;
        RECT 26.960000 5.715000 27.440000 5.805000 ;
        RECT 26.960000 4.563000 27.440000 4.653000 ;
        RECT 26.960000 3.411000 27.440000 3.501000 ;
        RECT 26.960000 2.259000 27.440000 2.349000 ;
        RECT 26.960000 1.107000 27.440000 1.197000 ;
        RECT 26.960000 -0.005000 27.440000 0.045000 ;
        RECT 18.960000 9.171000 19.440000 9.261000 ;
        RECT 18.960000 8.019000 19.440000 8.109000 ;
        RECT 18.960000 6.867000 19.440000 6.957000 ;
        RECT 18.960000 12.627000 19.440000 12.717000 ;
        RECT 18.960000 11.475000 19.440000 11.565000 ;
        RECT 18.960000 10.323000 19.440000 10.413000 ;
        RECT 26.960000 12.627000 27.440000 12.717000 ;
        RECT 26.960000 11.475000 27.440000 11.565000 ;
        RECT 26.960000 10.323000 27.440000 10.413000 ;
        RECT 26.960000 9.171000 27.440000 9.261000 ;
        RECT 26.960000 8.019000 27.440000 8.109000 ;
        RECT 26.960000 6.867000 27.440000 6.957000 ;
        RECT 2.960000 13.779000 3.440000 13.869000 ;
        RECT 2.960000 14.931000 3.440000 15.021000 ;
        RECT 2.960000 16.083000 3.440000 16.173000 ;
        RECT 2.960000 17.235000 3.440000 17.325000 ;
        RECT 2.960000 18.387000 3.440000 18.477000 ;
        RECT 2.960000 19.539000 3.440000 19.629000 ;
        RECT 10.960000 13.779000 11.440000 13.869000 ;
        RECT 10.960000 14.931000 11.440000 15.021000 ;
        RECT 10.960000 16.083000 11.440000 16.173000 ;
        RECT 10.960000 17.235000 11.440000 17.325000 ;
        RECT 10.960000 18.387000 11.440000 18.477000 ;
        RECT 10.960000 19.539000 11.440000 19.629000 ;
        RECT 2.960000 22.995000 3.440000 23.085000 ;
        RECT 2.960000 21.843000 3.440000 21.933000 ;
        RECT 2.960000 20.691000 3.440000 20.781000 ;
        RECT 2.960000 26.451000 3.440000 26.541000 ;
        RECT 2.960000 25.299000 3.440000 25.389000 ;
        RECT 2.960000 24.147000 3.440000 24.237000 ;
        RECT 10.960000 20.691000 11.440000 20.781000 ;
        RECT 10.960000 21.843000 11.440000 21.933000 ;
        RECT 10.960000 22.995000 11.440000 23.085000 ;
        RECT 10.960000 24.147000 11.440000 24.237000 ;
        RECT 10.960000 25.299000 11.440000 25.389000 ;
        RECT 10.960000 26.451000 11.440000 26.541000 ;
        RECT 18.960000 13.779000 19.440000 13.869000 ;
        RECT 18.960000 14.931000 19.440000 15.021000 ;
        RECT 18.960000 16.083000 19.440000 16.173000 ;
        RECT 18.960000 17.235000 19.440000 17.325000 ;
        RECT 18.960000 18.387000 19.440000 18.477000 ;
        RECT 18.960000 19.539000 19.440000 19.629000 ;
        RECT 26.960000 19.539000 27.440000 19.629000 ;
        RECT 26.960000 18.387000 27.440000 18.477000 ;
        RECT 26.960000 17.235000 27.440000 17.325000 ;
        RECT 26.960000 16.083000 27.440000 16.173000 ;
        RECT 26.960000 14.931000 27.440000 15.021000 ;
        RECT 26.960000 13.779000 27.440000 13.869000 ;
        RECT 18.960000 22.995000 19.440000 23.085000 ;
        RECT 18.960000 21.843000 19.440000 21.933000 ;
        RECT 18.960000 20.691000 19.440000 20.781000 ;
        RECT 18.960000 26.451000 19.440000 26.541000 ;
        RECT 18.960000 25.299000 19.440000 25.389000 ;
        RECT 18.960000 24.147000 19.440000 24.237000 ;
        RECT 26.960000 26.451000 27.440000 26.541000 ;
        RECT 26.960000 25.299000 27.440000 25.389000 ;
        RECT 26.960000 24.147000 27.440000 24.237000 ;
        RECT 26.960000 22.995000 27.440000 23.085000 ;
        RECT 26.960000 21.843000 27.440000 21.933000 ;
        RECT 26.960000 20.691000 27.440000 20.781000 ;
      LAYER M3 ;
        RECT 2.960000 1.107000 3.440000 1.197000 ;
        RECT 2.960000 -0.035000 3.440000 0.045000 ;
        RECT 2.960000 2.259000 3.440000 2.349000 ;
        RECT 2.960000 3.411000 3.440000 3.501000 ;
        RECT 2.960000 4.563000 3.440000 4.653000 ;
        RECT 2.960000 5.715000 3.440000 5.805000 ;
        RECT 10.960000 1.107000 11.440000 1.197000 ;
        RECT 10.960000 -0.035000 11.440000 0.045000 ;
        RECT 10.960000 2.259000 11.440000 2.349000 ;
        RECT 10.960000 3.411000 11.440000 3.501000 ;
        RECT 10.960000 4.563000 11.440000 4.653000 ;
        RECT 10.960000 5.715000 11.440000 5.805000 ;
        RECT 2.960000 9.171000 3.440000 9.261000 ;
        RECT 2.960000 6.867000 3.440000 6.957000 ;
        RECT 2.960000 8.019000 3.440000 8.109000 ;
        RECT 2.960000 12.627000 3.440000 12.717000 ;
        RECT 2.960000 11.475000 3.440000 11.565000 ;
        RECT 2.960000 10.323000 3.440000 10.413000 ;
        RECT 10.960000 8.019000 11.440000 8.109000 ;
        RECT 10.960000 6.867000 11.440000 6.957000 ;
        RECT 10.960000 9.171000 11.440000 9.261000 ;
        RECT 10.960000 10.323000 11.440000 10.413000 ;
        RECT 10.960000 11.475000 11.440000 11.565000 ;
        RECT 10.960000 12.627000 11.440000 12.717000 ;
        RECT 18.960000 -0.035000 19.440000 0.045000 ;
        RECT 18.960000 1.107000 19.440000 1.197000 ;
        RECT 18.960000 2.259000 19.440000 2.349000 ;
        RECT 18.960000 3.411000 19.440000 3.501000 ;
        RECT 18.960000 4.563000 19.440000 4.653000 ;
        RECT 18.960000 5.715000 19.440000 5.805000 ;
        RECT 26.960000 5.715000 27.440000 5.805000 ;
        RECT 26.960000 4.563000 27.440000 4.653000 ;
        RECT 26.960000 3.411000 27.440000 3.501000 ;
        RECT 26.960000 2.259000 27.440000 2.349000 ;
        RECT 26.960000 -0.035000 27.440000 0.045000 ;
        RECT 26.960000 1.107000 27.440000 1.197000 ;
        RECT 18.960000 9.171000 19.440000 9.261000 ;
        RECT 18.960000 6.867000 19.440000 6.957000 ;
        RECT 18.960000 8.019000 19.440000 8.109000 ;
        RECT 18.960000 12.627000 19.440000 12.717000 ;
        RECT 18.960000 11.475000 19.440000 11.565000 ;
        RECT 18.960000 10.323000 19.440000 10.413000 ;
        RECT 26.960000 12.627000 27.440000 12.717000 ;
        RECT 26.960000 11.475000 27.440000 11.565000 ;
        RECT 26.960000 10.323000 27.440000 10.413000 ;
        RECT 26.960000 9.171000 27.440000 9.261000 ;
        RECT 26.960000 6.867000 27.440000 6.957000 ;
        RECT 26.960000 8.019000 27.440000 8.109000 ;
        RECT 2.960000 14.931000 3.440000 15.021000 ;
        RECT 2.960000 13.779000 3.440000 13.869000 ;
        RECT 2.960000 16.083000 3.440000 16.173000 ;
        RECT 2.960000 17.235000 3.440000 17.325000 ;
        RECT 2.960000 18.387000 3.440000 18.477000 ;
        RECT 2.960000 19.539000 3.440000 19.629000 ;
        RECT 10.960000 14.931000 11.440000 15.021000 ;
        RECT 10.960000 13.779000 11.440000 13.869000 ;
        RECT 10.960000 16.083000 11.440000 16.173000 ;
        RECT 10.960000 17.235000 11.440000 17.325000 ;
        RECT 10.960000 18.387000 11.440000 18.477000 ;
        RECT 10.960000 19.539000 11.440000 19.629000 ;
        RECT 2.960000 22.995000 3.440000 23.085000 ;
        RECT 2.960000 20.691000 3.440000 20.781000 ;
        RECT 2.960000 21.843000 3.440000 21.933000 ;
        RECT 2.960000 26.451000 3.440000 26.541000 ;
        RECT 2.960000 25.299000 3.440000 25.389000 ;
        RECT 2.960000 24.147000 3.440000 24.237000 ;
        RECT 10.960000 21.843000 11.440000 21.933000 ;
        RECT 10.960000 20.691000 11.440000 20.781000 ;
        RECT 10.960000 22.995000 11.440000 23.085000 ;
        RECT 10.960000 24.147000 11.440000 24.237000 ;
        RECT 10.960000 25.299000 11.440000 25.389000 ;
        RECT 10.960000 26.451000 11.440000 26.541000 ;
        RECT 18.960000 13.779000 19.440000 13.869000 ;
        RECT 18.960000 14.931000 19.440000 15.021000 ;
        RECT 18.960000 16.083000 19.440000 16.173000 ;
        RECT 18.960000 17.235000 19.440000 17.325000 ;
        RECT 18.960000 18.387000 19.440000 18.477000 ;
        RECT 18.960000 19.539000 19.440000 19.629000 ;
        RECT 26.960000 19.539000 27.440000 19.629000 ;
        RECT 26.960000 18.387000 27.440000 18.477000 ;
        RECT 26.960000 17.235000 27.440000 17.325000 ;
        RECT 26.960000 16.083000 27.440000 16.173000 ;
        RECT 26.960000 13.779000 27.440000 13.869000 ;
        RECT 26.960000 14.931000 27.440000 15.021000 ;
        RECT 18.960000 22.995000 19.440000 23.085000 ;
        RECT 18.960000 20.691000 19.440000 20.781000 ;
        RECT 18.960000 21.843000 19.440000 21.933000 ;
        RECT 18.960000 26.451000 19.440000 26.541000 ;
        RECT 18.960000 25.299000 19.440000 25.389000 ;
        RECT 18.960000 24.147000 19.440000 24.237000 ;
        RECT 26.960000 26.451000 27.440000 26.541000 ;
        RECT 26.960000 25.299000 27.440000 25.389000 ;
        RECT 26.960000 24.147000 27.440000 24.237000 ;
        RECT 26.960000 22.995000 27.440000 23.085000 ;
        RECT 26.960000 20.691000 27.440000 20.781000 ;
        RECT 26.960000 21.843000 27.440000 21.933000 ;
      LAYER M4 ;
        RECT 2.960000 -0.035000 3.440000 0.045000 ;
        RECT 10.960000 -0.035000 11.440000 0.045000 ;
        RECT 18.960000 -0.035000 19.440000 0.045000 ;
        RECT 26.960000 -0.035000 27.440000 0.045000 ;
        RECT 2.960000 1.107000 3.440000 1.197000 ;
        RECT 2.960000 -0.017000 3.440000 0.063000 ;
        RECT 2.960000 2.259000 3.440000 2.349000 ;
        RECT 2.960000 3.411000 3.440000 3.501000 ;
        RECT 2.960000 4.563000 3.440000 4.653000 ;
        RECT 2.960000 5.715000 3.440000 5.805000 ;
        RECT 10.960000 1.107000 11.440000 1.197000 ;
        RECT 10.960000 -0.017000 11.440000 0.063000 ;
        RECT 10.960000 2.259000 11.440000 2.349000 ;
        RECT 10.960000 3.411000 11.440000 3.501000 ;
        RECT 10.960000 4.563000 11.440000 4.653000 ;
        RECT 10.960000 5.715000 11.440000 5.805000 ;
        RECT 2.960000 9.171000 3.440000 9.261000 ;
        RECT 2.960000 6.867000 3.440000 6.957000 ;
        RECT 2.960000 8.019000 3.440000 8.109000 ;
        RECT 2.960000 12.627000 3.440000 12.717000 ;
        RECT 2.960000 11.475000 3.440000 11.565000 ;
        RECT 2.960000 10.323000 3.440000 10.413000 ;
        RECT 10.960000 8.019000 11.440000 8.109000 ;
        RECT 10.960000 6.867000 11.440000 6.957000 ;
        RECT 10.960000 9.171000 11.440000 9.261000 ;
        RECT 10.960000 10.323000 11.440000 10.413000 ;
        RECT 10.960000 11.475000 11.440000 11.565000 ;
        RECT 10.960000 12.627000 11.440000 12.717000 ;
        RECT 18.960000 -0.017000 19.440000 0.063000 ;
        RECT 18.960000 1.107000 19.440000 1.197000 ;
        RECT 18.960000 2.259000 19.440000 2.349000 ;
        RECT 18.960000 3.411000 19.440000 3.501000 ;
        RECT 18.960000 4.563000 19.440000 4.653000 ;
        RECT 18.960000 5.715000 19.440000 5.805000 ;
        RECT 26.960000 5.715000 27.440000 5.805000 ;
        RECT 26.960000 4.563000 27.440000 4.653000 ;
        RECT 26.960000 3.411000 27.440000 3.501000 ;
        RECT 26.960000 2.259000 27.440000 2.349000 ;
        RECT 26.960000 -0.017000 27.440000 0.063000 ;
        RECT 26.960000 1.107000 27.440000 1.197000 ;
        RECT 18.960000 9.171000 19.440000 9.261000 ;
        RECT 18.960000 6.867000 19.440000 6.957000 ;
        RECT 18.960000 8.019000 19.440000 8.109000 ;
        RECT 18.960000 12.627000 19.440000 12.717000 ;
        RECT 18.960000 11.475000 19.440000 11.565000 ;
        RECT 18.960000 10.323000 19.440000 10.413000 ;
        RECT 26.960000 12.627000 27.440000 12.717000 ;
        RECT 26.960000 11.475000 27.440000 11.565000 ;
        RECT 26.960000 10.323000 27.440000 10.413000 ;
        RECT 26.960000 9.171000 27.440000 9.261000 ;
        RECT 26.960000 6.867000 27.440000 6.957000 ;
        RECT 26.960000 8.019000 27.440000 8.109000 ;
        RECT 2.960000 14.931000 3.440000 15.021000 ;
        RECT 2.960000 13.779000 3.440000 13.869000 ;
        RECT 2.960000 16.083000 3.440000 16.173000 ;
        RECT 2.960000 17.235000 3.440000 17.325000 ;
        RECT 2.960000 18.387000 3.440000 18.477000 ;
        RECT 2.960000 19.539000 3.440000 19.629000 ;
        RECT 10.960000 14.931000 11.440000 15.021000 ;
        RECT 10.960000 13.779000 11.440000 13.869000 ;
        RECT 10.960000 16.083000 11.440000 16.173000 ;
        RECT 10.960000 17.235000 11.440000 17.325000 ;
        RECT 10.960000 18.387000 11.440000 18.477000 ;
        RECT 10.960000 19.539000 11.440000 19.629000 ;
        RECT 2.960000 22.995000 3.440000 23.085000 ;
        RECT 2.960000 20.691000 3.440000 20.781000 ;
        RECT 2.960000 21.843000 3.440000 21.933000 ;
        RECT 2.960000 26.451000 3.440000 26.541000 ;
        RECT 2.960000 25.299000 3.440000 25.389000 ;
        RECT 2.960000 24.147000 3.440000 24.237000 ;
        RECT 10.960000 21.843000 11.440000 21.933000 ;
        RECT 10.960000 20.691000 11.440000 20.781000 ;
        RECT 10.960000 22.995000 11.440000 23.085000 ;
        RECT 10.960000 24.147000 11.440000 24.237000 ;
        RECT 10.960000 25.299000 11.440000 25.389000 ;
        RECT 10.960000 26.451000 11.440000 26.541000 ;
        RECT 18.960000 13.779000 19.440000 13.869000 ;
        RECT 18.960000 14.931000 19.440000 15.021000 ;
        RECT 18.960000 16.083000 19.440000 16.173000 ;
        RECT 18.960000 17.235000 19.440000 17.325000 ;
        RECT 18.960000 18.387000 19.440000 18.477000 ;
        RECT 18.960000 19.539000 19.440000 19.629000 ;
        RECT 26.960000 19.539000 27.440000 19.629000 ;
        RECT 26.960000 18.387000 27.440000 18.477000 ;
        RECT 26.960000 17.235000 27.440000 17.325000 ;
        RECT 26.960000 16.083000 27.440000 16.173000 ;
        RECT 26.960000 13.779000 27.440000 13.869000 ;
        RECT 26.960000 14.931000 27.440000 15.021000 ;
        RECT 18.960000 22.995000 19.440000 23.085000 ;
        RECT 18.960000 20.691000 19.440000 20.781000 ;
        RECT 18.960000 21.843000 19.440000 21.933000 ;
        RECT 18.960000 26.451000 19.440000 26.541000 ;
        RECT 18.960000 25.299000 19.440000 25.389000 ;
        RECT 18.960000 24.147000 19.440000 24.237000 ;
        RECT 26.960000 26.451000 27.440000 26.541000 ;
        RECT 26.960000 25.299000 27.440000 25.389000 ;
        RECT 26.960000 24.147000 27.440000 24.237000 ;
        RECT 26.960000 22.995000 27.440000 23.085000 ;
        RECT 26.960000 20.691000 27.440000 20.781000 ;
        RECT 26.960000 21.843000 27.440000 21.933000 ;
      LAYER M5 ;
        RECT 26.960000 0.000000 27.440000 27.072000 ;
        RECT 18.960000 0.000000 19.440000 27.072000 ;
        RECT 10.960000 0.000000 11.440000 27.072000 ;
        RECT 2.960000 0.000000 3.440000 27.072000 ;
        RECT 2.960000 -0.017000 3.440000 0.063000 ;
        RECT 10.960000 -0.017000 11.440000 0.063000 ;
        RECT 18.960000 -0.017000 19.440000 0.063000 ;
        RECT 26.960000 -0.017000 27.440000 0.063000 ;
    END
# end of P/G power stripe data as pin

  END VDD
  PIN VSS
    DIRECTION INOUT ;
    USE GROUND ;
    PORT
      LAYER M5 ;
        RECT 19.840000 0.000000 20.320000 27.072000 ;
    END
    PORT
      LAYER M5 ;
        RECT 11.840000 0.000000 12.320000 27.072000 ;
    END
    PORT
      LAYER M5 ;
        RECT 3.840000 0.000000 4.320000 27.072000 ;
    END
    PORT
      LAYER M5 ;
        RECT 19.840000 26.592000 20.320000 27.072000 ;
    END
    PORT
      LAYER M5 ;
        RECT 19.840000 0.000000 20.320000 0.480000 ;
    END
    PORT
      LAYER M5 ;
        RECT 11.840000 26.592000 12.320000 27.072000 ;
    END
    PORT
      LAYER M5 ;
        RECT 11.840000 0.000000 12.320000 0.480000 ;
    END
    PORT
      LAYER M5 ;
        RECT 3.840000 26.592000 4.320000 27.072000 ;
    END
    PORT
      LAYER M5 ;
        RECT 3.840000 0.000000 4.320000 0.480000 ;
    END

# P/G power stripe data as pin
    PORT
      LAYER M1 ;
        RECT 0.000000 0.531000 27.540000 0.621000 ;
        RECT 0.000000 1.683000 27.540000 1.773000 ;
        RECT 0.000000 2.835000 27.540000 2.925000 ;
        RECT 0.000000 3.987000 27.540000 4.077000 ;
        RECT 0.000000 5.139000 27.540000 5.229000 ;
        RECT 0.000000 6.291000 27.540000 6.381000 ;
        RECT 0.000000 7.443000 27.540000 7.533000 ;
        RECT 0.000000 8.595000 27.540000 8.685000 ;
        RECT 0.000000 9.747000 27.540000 9.837000 ;
        RECT 0.000000 10.899000 27.540000 10.989000 ;
        RECT 0.000000 12.051000 27.540000 12.141000 ;
        RECT 0.000000 13.203000 27.540000 13.293000 ;
        RECT 0.000000 14.355000 27.540000 14.445000 ;
        RECT 0.000000 15.507000 27.540000 15.597000 ;
        RECT 0.000000 16.659000 27.540000 16.749000 ;
        RECT 0.000000 17.811000 27.540000 17.901000 ;
        RECT 0.000000 18.963000 27.540000 19.053000 ;
        RECT 0.000000 20.115000 27.540000 20.205000 ;
        RECT 0.000000 27.027000 27.540000 27.117000 ;
        RECT 0.000000 25.875000 27.540000 25.965000 ;
        RECT 0.000000 24.723000 27.540000 24.813000 ;
        RECT 0.000000 23.571000 27.540000 23.661000 ;
        RECT 0.000000 22.419000 27.540000 22.509000 ;
        RECT 0.000000 21.267000 27.540000 21.357000 ;
      LAYER M2 ;
        RECT 3.840000 2.835000 4.320000 2.925000 ;
        RECT 3.840000 1.683000 4.320000 1.773000 ;
        RECT 3.840000 0.531000 4.320000 0.621000 ;
        RECT 3.840000 6.291000 4.320000 6.381000 ;
        RECT 3.840000 5.139000 4.320000 5.229000 ;
        RECT 3.840000 3.987000 4.320000 4.077000 ;
        RECT 11.840000 2.835000 12.320000 2.925000 ;
        RECT 11.840000 1.683000 12.320000 1.773000 ;
        RECT 11.840000 0.531000 12.320000 0.621000 ;
        RECT 11.840000 6.291000 12.320000 6.381000 ;
        RECT 11.840000 5.139000 12.320000 5.229000 ;
        RECT 11.840000 3.987000 12.320000 4.077000 ;
        RECT 3.840000 9.747000 4.320000 9.837000 ;
        RECT 3.840000 8.595000 4.320000 8.685000 ;
        RECT 3.840000 7.443000 4.320000 7.533000 ;
        RECT 3.840000 13.203000 4.320000 13.293000 ;
        RECT 3.840000 12.051000 4.320000 12.141000 ;
        RECT 3.840000 10.899000 4.320000 10.989000 ;
        RECT 11.840000 9.747000 12.320000 9.837000 ;
        RECT 11.840000 8.595000 12.320000 8.685000 ;
        RECT 11.840000 7.443000 12.320000 7.533000 ;
        RECT 11.840000 13.203000 12.320000 13.293000 ;
        RECT 11.840000 12.051000 12.320000 12.141000 ;
        RECT 11.840000 10.899000 12.320000 10.989000 ;
        RECT 19.840000 2.835000 20.320000 2.925000 ;
        RECT 19.840000 1.683000 20.320000 1.773000 ;
        RECT 19.840000 0.531000 20.320000 0.621000 ;
        RECT 19.840000 6.291000 20.320000 6.381000 ;
        RECT 19.840000 5.139000 20.320000 5.229000 ;
        RECT 19.840000 3.987000 20.320000 4.077000 ;
        RECT 19.840000 9.747000 20.320000 9.837000 ;
        RECT 19.840000 8.595000 20.320000 8.685000 ;
        RECT 19.840000 7.443000 20.320000 7.533000 ;
        RECT 19.840000 13.203000 20.320000 13.293000 ;
        RECT 19.840000 12.051000 20.320000 12.141000 ;
        RECT 19.840000 10.899000 20.320000 10.989000 ;
        RECT 3.840000 16.659000 4.320000 16.749000 ;
        RECT 3.840000 15.507000 4.320000 15.597000 ;
        RECT 3.840000 14.355000 4.320000 14.445000 ;
        RECT 3.840000 20.115000 4.320000 20.205000 ;
        RECT 3.840000 18.963000 4.320000 19.053000 ;
        RECT 3.840000 17.811000 4.320000 17.901000 ;
        RECT 11.840000 16.659000 12.320000 16.749000 ;
        RECT 11.840000 15.507000 12.320000 15.597000 ;
        RECT 11.840000 14.355000 12.320000 14.445000 ;
        RECT 11.840000 20.115000 12.320000 20.205000 ;
        RECT 11.840000 18.963000 12.320000 19.053000 ;
        RECT 11.840000 17.811000 12.320000 17.901000 ;
        RECT 3.840000 23.571000 4.320000 23.661000 ;
        RECT 3.840000 22.419000 4.320000 22.509000 ;
        RECT 3.840000 21.267000 4.320000 21.357000 ;
        RECT 3.840000 27.027000 4.320000 27.077000 ;
        RECT 3.840000 25.875000 4.320000 25.965000 ;
        RECT 3.840000 24.723000 4.320000 24.813000 ;
        RECT 11.840000 23.571000 12.320000 23.661000 ;
        RECT 11.840000 22.419000 12.320000 22.509000 ;
        RECT 11.840000 21.267000 12.320000 21.357000 ;
        RECT 11.840000 27.027000 12.320000 27.077000 ;
        RECT 11.840000 25.875000 12.320000 25.965000 ;
        RECT 11.840000 24.723000 12.320000 24.813000 ;
        RECT 19.840000 16.659000 20.320000 16.749000 ;
        RECT 19.840000 15.507000 20.320000 15.597000 ;
        RECT 19.840000 14.355000 20.320000 14.445000 ;
        RECT 19.840000 20.115000 20.320000 20.205000 ;
        RECT 19.840000 18.963000 20.320000 19.053000 ;
        RECT 19.840000 17.811000 20.320000 17.901000 ;
        RECT 19.840000 23.571000 20.320000 23.661000 ;
        RECT 19.840000 22.419000 20.320000 22.509000 ;
        RECT 19.840000 21.267000 20.320000 21.357000 ;
        RECT 19.840000 27.027000 20.320000 27.077000 ;
        RECT 19.840000 25.875000 20.320000 25.965000 ;
        RECT 19.840000 24.723000 20.320000 24.813000 ;
      LAYER M3 ;
        RECT 3.840000 2.835000 4.320000 2.925000 ;
        RECT 3.840000 0.531000 4.320000 0.621000 ;
        RECT 3.840000 1.683000 4.320000 1.773000 ;
        RECT 3.840000 6.291000 4.320000 6.381000 ;
        RECT 3.840000 5.139000 4.320000 5.229000 ;
        RECT 3.840000 3.987000 4.320000 4.077000 ;
        RECT 11.840000 2.835000 12.320000 2.925000 ;
        RECT 11.840000 0.531000 12.320000 0.621000 ;
        RECT 11.840000 1.683000 12.320000 1.773000 ;
        RECT 11.840000 6.291000 12.320000 6.381000 ;
        RECT 11.840000 5.139000 12.320000 5.229000 ;
        RECT 11.840000 3.987000 12.320000 4.077000 ;
        RECT 3.840000 9.747000 4.320000 9.837000 ;
        RECT 3.840000 7.443000 4.320000 7.533000 ;
        RECT 3.840000 8.595000 4.320000 8.685000 ;
        RECT 3.840000 13.203000 4.320000 13.293000 ;
        RECT 3.840000 12.051000 4.320000 12.141000 ;
        RECT 3.840000 10.899000 4.320000 10.989000 ;
        RECT 11.840000 9.747000 12.320000 9.837000 ;
        RECT 11.840000 7.443000 12.320000 7.533000 ;
        RECT 11.840000 8.595000 12.320000 8.685000 ;
        RECT 11.840000 13.203000 12.320000 13.293000 ;
        RECT 11.840000 12.051000 12.320000 12.141000 ;
        RECT 11.840000 10.899000 12.320000 10.989000 ;
        RECT 19.840000 2.835000 20.320000 2.925000 ;
        RECT 19.840000 0.531000 20.320000 0.621000 ;
        RECT 19.840000 1.683000 20.320000 1.773000 ;
        RECT 19.840000 6.291000 20.320000 6.381000 ;
        RECT 19.840000 5.139000 20.320000 5.229000 ;
        RECT 19.840000 3.987000 20.320000 4.077000 ;
        RECT 19.840000 9.747000 20.320000 9.837000 ;
        RECT 19.840000 7.443000 20.320000 7.533000 ;
        RECT 19.840000 8.595000 20.320000 8.685000 ;
        RECT 19.840000 13.203000 20.320000 13.293000 ;
        RECT 19.840000 12.051000 20.320000 12.141000 ;
        RECT 19.840000 10.899000 20.320000 10.989000 ;
        RECT 3.840000 16.659000 4.320000 16.749000 ;
        RECT 3.840000 14.355000 4.320000 14.445000 ;
        RECT 3.840000 15.507000 4.320000 15.597000 ;
        RECT 3.840000 20.115000 4.320000 20.205000 ;
        RECT 3.840000 18.963000 4.320000 19.053000 ;
        RECT 3.840000 17.811000 4.320000 17.901000 ;
        RECT 11.840000 16.659000 12.320000 16.749000 ;
        RECT 11.840000 14.355000 12.320000 14.445000 ;
        RECT 11.840000 15.507000 12.320000 15.597000 ;
        RECT 11.840000 20.115000 12.320000 20.205000 ;
        RECT 11.840000 18.963000 12.320000 19.053000 ;
        RECT 11.840000 17.811000 12.320000 17.901000 ;
        RECT 3.840000 23.571000 4.320000 23.661000 ;
        RECT 3.840000 21.267000 4.320000 21.357000 ;
        RECT 3.840000 22.419000 4.320000 22.509000 ;
        RECT 3.840000 27.027000 4.320000 27.107000 ;
        RECT 3.840000 25.875000 4.320000 25.965000 ;
        RECT 3.840000 24.723000 4.320000 24.813000 ;
        RECT 11.840000 23.571000 12.320000 23.661000 ;
        RECT 11.840000 21.267000 12.320000 21.357000 ;
        RECT 11.840000 22.419000 12.320000 22.509000 ;
        RECT 11.840000 27.027000 12.320000 27.107000 ;
        RECT 11.840000 25.875000 12.320000 25.965000 ;
        RECT 11.840000 24.723000 12.320000 24.813000 ;
        RECT 19.840000 16.659000 20.320000 16.749000 ;
        RECT 19.840000 14.355000 20.320000 14.445000 ;
        RECT 19.840000 15.507000 20.320000 15.597000 ;
        RECT 19.840000 20.115000 20.320000 20.205000 ;
        RECT 19.840000 18.963000 20.320000 19.053000 ;
        RECT 19.840000 17.811000 20.320000 17.901000 ;
        RECT 19.840000 23.571000 20.320000 23.661000 ;
        RECT 19.840000 21.267000 20.320000 21.357000 ;
        RECT 19.840000 22.419000 20.320000 22.509000 ;
        RECT 19.840000 27.027000 20.320000 27.107000 ;
        RECT 19.840000 25.875000 20.320000 25.965000 ;
        RECT 19.840000 24.723000 20.320000 24.813000 ;
      LAYER M4 ;
        RECT 3.840000 27.027000 4.320000 27.107000 ;
        RECT 11.840000 27.027000 12.320000 27.107000 ;
        RECT 19.840000 27.027000 20.320000 27.107000 ;
        RECT 3.840000 2.835000 4.320000 2.925000 ;
        RECT 3.840000 0.531000 4.320000 0.621000 ;
        RECT 3.840000 1.683000 4.320000 1.773000 ;
        RECT 3.840000 6.291000 4.320000 6.381000 ;
        RECT 3.840000 5.139000 4.320000 5.229000 ;
        RECT 3.840000 3.987000 4.320000 4.077000 ;
        RECT 11.840000 2.835000 12.320000 2.925000 ;
        RECT 11.840000 0.531000 12.320000 0.621000 ;
        RECT 11.840000 1.683000 12.320000 1.773000 ;
        RECT 11.840000 6.291000 12.320000 6.381000 ;
        RECT 11.840000 5.139000 12.320000 5.229000 ;
        RECT 11.840000 3.987000 12.320000 4.077000 ;
        RECT 3.840000 9.747000 4.320000 9.837000 ;
        RECT 3.840000 7.443000 4.320000 7.533000 ;
        RECT 3.840000 8.595000 4.320000 8.685000 ;
        RECT 3.840000 13.203000 4.320000 13.293000 ;
        RECT 3.840000 12.051000 4.320000 12.141000 ;
        RECT 3.840000 10.899000 4.320000 10.989000 ;
        RECT 11.840000 9.747000 12.320000 9.837000 ;
        RECT 11.840000 7.443000 12.320000 7.533000 ;
        RECT 11.840000 8.595000 12.320000 8.685000 ;
        RECT 11.840000 13.203000 12.320000 13.293000 ;
        RECT 11.840000 12.051000 12.320000 12.141000 ;
        RECT 11.840000 10.899000 12.320000 10.989000 ;
        RECT 19.840000 2.835000 20.320000 2.925000 ;
        RECT 19.840000 0.531000 20.320000 0.621000 ;
        RECT 19.840000 1.683000 20.320000 1.773000 ;
        RECT 19.840000 6.291000 20.320000 6.381000 ;
        RECT 19.840000 5.139000 20.320000 5.229000 ;
        RECT 19.840000 3.987000 20.320000 4.077000 ;
        RECT 19.840000 9.747000 20.320000 9.837000 ;
        RECT 19.840000 7.443000 20.320000 7.533000 ;
        RECT 19.840000 8.595000 20.320000 8.685000 ;
        RECT 19.840000 13.203000 20.320000 13.293000 ;
        RECT 19.840000 12.051000 20.320000 12.141000 ;
        RECT 19.840000 10.899000 20.320000 10.989000 ;
        RECT 3.840000 16.659000 4.320000 16.749000 ;
        RECT 3.840000 14.355000 4.320000 14.445000 ;
        RECT 3.840000 15.507000 4.320000 15.597000 ;
        RECT 3.840000 20.115000 4.320000 20.205000 ;
        RECT 3.840000 18.963000 4.320000 19.053000 ;
        RECT 3.840000 17.811000 4.320000 17.901000 ;
        RECT 11.840000 16.659000 12.320000 16.749000 ;
        RECT 11.840000 14.355000 12.320000 14.445000 ;
        RECT 11.840000 15.507000 12.320000 15.597000 ;
        RECT 11.840000 20.115000 12.320000 20.205000 ;
        RECT 11.840000 18.963000 12.320000 19.053000 ;
        RECT 11.840000 17.811000 12.320000 17.901000 ;
        RECT 3.840000 23.571000 4.320000 23.661000 ;
        RECT 3.840000 21.267000 4.320000 21.357000 ;
        RECT 3.840000 22.419000 4.320000 22.509000 ;
        RECT 3.840000 27.010000 4.320000 27.090000 ;
        RECT 3.840000 25.875000 4.320000 25.965000 ;
        RECT 3.840000 24.723000 4.320000 24.813000 ;
        RECT 11.840000 23.571000 12.320000 23.661000 ;
        RECT 11.840000 21.267000 12.320000 21.357000 ;
        RECT 11.840000 22.419000 12.320000 22.509000 ;
        RECT 11.840000 27.010000 12.320000 27.090000 ;
        RECT 11.840000 25.875000 12.320000 25.965000 ;
        RECT 11.840000 24.723000 12.320000 24.813000 ;
        RECT 19.840000 16.659000 20.320000 16.749000 ;
        RECT 19.840000 14.355000 20.320000 14.445000 ;
        RECT 19.840000 15.507000 20.320000 15.597000 ;
        RECT 19.840000 20.115000 20.320000 20.205000 ;
        RECT 19.840000 18.963000 20.320000 19.053000 ;
        RECT 19.840000 17.811000 20.320000 17.901000 ;
        RECT 19.840000 23.571000 20.320000 23.661000 ;
        RECT 19.840000 21.267000 20.320000 21.357000 ;
        RECT 19.840000 22.419000 20.320000 22.509000 ;
        RECT 19.840000 27.010000 20.320000 27.090000 ;
        RECT 19.840000 25.875000 20.320000 25.965000 ;
        RECT 19.840000 24.723000 20.320000 24.813000 ;
      LAYER M5 ;
        RECT 19.840000 0.000000 20.320000 27.072000 ;
        RECT 11.840000 0.000000 12.320000 27.072000 ;
        RECT 3.840000 0.000000 4.320000 27.072000 ;
        RECT 3.840000 27.010000 4.320000 27.090000 ;
        RECT 11.840000 27.010000 12.320000 27.090000 ;
        RECT 19.840000 27.010000 20.320000 27.090000 ;
    END
# end of P/G power stripe data as pin

  END VSS
  OBS
    LAYER M2 ;
      RECT 20.376000 26.995000 27.540000 27.072000 ;
      RECT 12.376000 26.995000 19.784000 27.072000 ;
      RECT 4.376000 26.995000 11.784000 27.072000 ;
      RECT 0.000000 26.995000 3.784000 27.072000 ;
      RECT 0.000000 26.622000 27.540000 26.995000 ;
      RECT 27.521000 26.370000 27.540000 26.622000 ;
      RECT 19.521000 26.370000 26.879000 26.622000 ;
      RECT 11.521000 26.370000 18.879000 26.622000 ;
      RECT 3.521000 26.370000 10.879000 26.622000 ;
      RECT 0.000000 26.370000 2.879000 26.622000 ;
      RECT 0.000000 26.046000 27.540000 26.370000 ;
      RECT 20.401000 25.794000 27.540000 26.046000 ;
      RECT 12.401000 25.794000 19.759000 26.046000 ;
      RECT 4.401000 25.794000 11.759000 26.046000 ;
      RECT 0.000000 25.794000 3.759000 26.046000 ;
      RECT 0.000000 25.470000 27.540000 25.794000 ;
      RECT 27.521000 25.218000 27.540000 25.470000 ;
      RECT 19.521000 25.218000 26.879000 25.470000 ;
      RECT 11.521000 25.218000 18.879000 25.470000 ;
      RECT 3.521000 25.218000 10.879000 25.470000 ;
      RECT 0.000000 25.218000 2.879000 25.470000 ;
      RECT 0.000000 24.894000 27.540000 25.218000 ;
      RECT 20.401000 24.642000 27.540000 24.894000 ;
      RECT 12.401000 24.642000 19.759000 24.894000 ;
      RECT 4.401000 24.642000 11.759000 24.894000 ;
      RECT 0.000000 24.642000 3.759000 24.894000 ;
      RECT 0.000000 24.318000 27.540000 24.642000 ;
      RECT 27.521000 24.066000 27.540000 24.318000 ;
      RECT 19.521000 24.066000 26.879000 24.318000 ;
      RECT 11.521000 24.066000 18.879000 24.318000 ;
      RECT 3.521000 24.066000 10.879000 24.318000 ;
      RECT 0.000000 24.066000 2.879000 24.318000 ;
      RECT 0.000000 23.742000 27.540000 24.066000 ;
      RECT 20.401000 23.490000 27.540000 23.742000 ;
      RECT 12.401000 23.490000 19.759000 23.742000 ;
      RECT 4.401000 23.490000 11.759000 23.742000 ;
      RECT 0.000000 23.490000 3.759000 23.742000 ;
      RECT 0.000000 23.166000 27.540000 23.490000 ;
      RECT 27.521000 22.914000 27.540000 23.166000 ;
      RECT 19.521000 22.914000 26.879000 23.166000 ;
      RECT 11.521000 22.914000 18.879000 23.166000 ;
      RECT 3.521000 22.914000 10.879000 23.166000 ;
      RECT 0.000000 22.914000 2.879000 23.166000 ;
      RECT 0.000000 22.590000 27.540000 22.914000 ;
      RECT 20.401000 22.338000 27.540000 22.590000 ;
      RECT 12.401000 22.338000 19.759000 22.590000 ;
      RECT 4.401000 22.338000 11.759000 22.590000 ;
      RECT 0.000000 22.338000 3.759000 22.590000 ;
      RECT 0.000000 22.014000 27.540000 22.338000 ;
      RECT 27.521000 21.762000 27.540000 22.014000 ;
      RECT 19.521000 21.762000 26.879000 22.014000 ;
      RECT 11.521000 21.762000 18.879000 22.014000 ;
      RECT 3.521000 21.762000 10.879000 22.014000 ;
      RECT 0.000000 21.762000 2.879000 22.014000 ;
      RECT 0.000000 21.438000 27.540000 21.762000 ;
      RECT 20.401000 21.186000 27.540000 21.438000 ;
      RECT 12.401000 21.186000 19.759000 21.438000 ;
      RECT 4.401000 21.186000 11.759000 21.438000 ;
      RECT 0.000000 21.186000 3.759000 21.438000 ;
      RECT 0.000000 20.862000 27.540000 21.186000 ;
      RECT 27.521000 20.610000 27.540000 20.862000 ;
      RECT 19.521000 20.610000 26.879000 20.862000 ;
      RECT 11.521000 20.610000 18.879000 20.862000 ;
      RECT 3.521000 20.610000 10.879000 20.862000 ;
      RECT 0.000000 20.610000 2.879000 20.862000 ;
      RECT 0.000000 20.286000 27.540000 20.610000 ;
      RECT 20.401000 20.034000 27.540000 20.286000 ;
      RECT 12.401000 20.034000 19.759000 20.286000 ;
      RECT 4.401000 20.034000 11.759000 20.286000 ;
      RECT 0.000000 20.034000 3.759000 20.286000 ;
      RECT 0.000000 19.710000 27.540000 20.034000 ;
      RECT 27.521000 19.458000 27.540000 19.710000 ;
      RECT 19.521000 19.458000 26.879000 19.710000 ;
      RECT 11.521000 19.458000 18.879000 19.710000 ;
      RECT 3.521000 19.458000 10.879000 19.710000 ;
      RECT 0.000000 19.458000 2.879000 19.710000 ;
      RECT 0.000000 19.134000 27.540000 19.458000 ;
      RECT 20.401000 18.882000 27.540000 19.134000 ;
      RECT 12.401000 18.882000 19.759000 19.134000 ;
      RECT 4.401000 18.882000 11.759000 19.134000 ;
      RECT 0.000000 18.882000 3.759000 19.134000 ;
      RECT 0.000000 18.558000 27.540000 18.882000 ;
      RECT 27.521000 18.306000 27.540000 18.558000 ;
      RECT 19.521000 18.306000 26.879000 18.558000 ;
      RECT 11.521000 18.306000 18.879000 18.558000 ;
      RECT 3.521000 18.306000 10.879000 18.558000 ;
      RECT 0.000000 18.306000 2.879000 18.558000 ;
      RECT 0.000000 17.982000 27.540000 18.306000 ;
      RECT 20.401000 17.730000 27.540000 17.982000 ;
      RECT 12.401000 17.730000 19.759000 17.982000 ;
      RECT 4.401000 17.730000 11.759000 17.982000 ;
      RECT 0.000000 17.730000 3.759000 17.982000 ;
      RECT 0.000000 17.406000 27.540000 17.730000 ;
      RECT 27.521000 17.154000 27.540000 17.406000 ;
      RECT 19.521000 17.154000 26.879000 17.406000 ;
      RECT 11.521000 17.154000 18.879000 17.406000 ;
      RECT 3.521000 17.154000 10.879000 17.406000 ;
      RECT 0.000000 17.154000 2.879000 17.406000 ;
      RECT 0.000000 16.830000 27.540000 17.154000 ;
      RECT 20.401000 16.578000 27.540000 16.830000 ;
      RECT 12.401000 16.578000 19.759000 16.830000 ;
      RECT 4.401000 16.578000 11.759000 16.830000 ;
      RECT 0.000000 16.578000 3.759000 16.830000 ;
      RECT 0.000000 16.254000 27.540000 16.578000 ;
      RECT 27.521000 16.002000 27.540000 16.254000 ;
      RECT 19.521000 16.002000 26.879000 16.254000 ;
      RECT 11.521000 16.002000 18.879000 16.254000 ;
      RECT 3.521000 16.002000 10.879000 16.254000 ;
      RECT 0.000000 16.002000 2.879000 16.254000 ;
      RECT 0.000000 15.678000 27.540000 16.002000 ;
      RECT 20.401000 15.426000 27.540000 15.678000 ;
      RECT 12.401000 15.426000 19.759000 15.678000 ;
      RECT 4.401000 15.426000 11.759000 15.678000 ;
      RECT 0.000000 15.426000 3.759000 15.678000 ;
      RECT 0.000000 15.102000 27.540000 15.426000 ;
      RECT 27.521000 14.850000 27.540000 15.102000 ;
      RECT 19.521000 14.850000 26.879000 15.102000 ;
      RECT 11.521000 14.850000 18.879000 15.102000 ;
      RECT 3.521000 14.850000 10.879000 15.102000 ;
      RECT 0.000000 14.850000 2.879000 15.102000 ;
      RECT 0.000000 14.526000 27.540000 14.850000 ;
      RECT 20.401000 14.274000 27.540000 14.526000 ;
      RECT 12.401000 14.274000 19.759000 14.526000 ;
      RECT 4.401000 14.274000 11.759000 14.526000 ;
      RECT 0.000000 14.274000 3.759000 14.526000 ;
      RECT 0.000000 13.950000 27.540000 14.274000 ;
      RECT 27.521000 13.698000 27.540000 13.950000 ;
      RECT 19.521000 13.698000 26.879000 13.950000 ;
      RECT 11.521000 13.698000 18.879000 13.950000 ;
      RECT 3.521000 13.698000 10.879000 13.950000 ;
      RECT 0.000000 13.698000 2.879000 13.950000 ;
      RECT 0.000000 13.374000 27.540000 13.698000 ;
      RECT 20.401000 13.122000 27.540000 13.374000 ;
      RECT 12.401000 13.122000 19.759000 13.374000 ;
      RECT 4.401000 13.122000 11.759000 13.374000 ;
      RECT 0.000000 13.122000 3.759000 13.374000 ;
      RECT 0.000000 12.798000 27.540000 13.122000 ;
      RECT 27.521000 12.546000 27.540000 12.798000 ;
      RECT 19.521000 12.546000 26.879000 12.798000 ;
      RECT 11.521000 12.546000 18.879000 12.798000 ;
      RECT 3.521000 12.546000 10.879000 12.798000 ;
      RECT 0.000000 12.546000 2.879000 12.798000 ;
      RECT 0.000000 12.222000 27.540000 12.546000 ;
      RECT 20.401000 11.970000 27.540000 12.222000 ;
      RECT 12.401000 11.970000 19.759000 12.222000 ;
      RECT 4.401000 11.970000 11.759000 12.222000 ;
      RECT 0.000000 11.970000 3.759000 12.222000 ;
      RECT 0.000000 11.646000 27.540000 11.970000 ;
      RECT 27.521000 11.394000 27.540000 11.646000 ;
      RECT 19.521000 11.394000 26.879000 11.646000 ;
      RECT 11.521000 11.394000 18.879000 11.646000 ;
      RECT 3.521000 11.394000 10.879000 11.646000 ;
      RECT 0.000000 11.394000 2.879000 11.646000 ;
      RECT 0.000000 11.070000 27.540000 11.394000 ;
      RECT 20.401000 10.818000 27.540000 11.070000 ;
      RECT 12.401000 10.818000 19.759000 11.070000 ;
      RECT 4.401000 10.818000 11.759000 11.070000 ;
      RECT 0.000000 10.818000 3.759000 11.070000 ;
      RECT 0.000000 10.494000 27.540000 10.818000 ;
      RECT 27.521000 10.242000 27.540000 10.494000 ;
      RECT 19.521000 10.242000 26.879000 10.494000 ;
      RECT 11.521000 10.242000 18.879000 10.494000 ;
      RECT 3.521000 10.242000 10.879000 10.494000 ;
      RECT 0.000000 10.242000 2.879000 10.494000 ;
      RECT 0.000000 9.918000 27.540000 10.242000 ;
      RECT 20.401000 9.666000 27.540000 9.918000 ;
      RECT 12.401000 9.666000 19.759000 9.918000 ;
      RECT 4.401000 9.666000 11.759000 9.918000 ;
      RECT 0.000000 9.666000 3.759000 9.918000 ;
      RECT 0.000000 9.342000 27.540000 9.666000 ;
      RECT 27.521000 9.090000 27.540000 9.342000 ;
      RECT 19.521000 9.090000 26.879000 9.342000 ;
      RECT 11.521000 9.090000 18.879000 9.342000 ;
      RECT 3.521000 9.090000 10.879000 9.342000 ;
      RECT 0.000000 9.090000 2.879000 9.342000 ;
      RECT 0.000000 8.766000 27.540000 9.090000 ;
      RECT 20.401000 8.514000 27.540000 8.766000 ;
      RECT 12.401000 8.514000 19.759000 8.766000 ;
      RECT 4.401000 8.514000 11.759000 8.766000 ;
      RECT 0.000000 8.514000 3.759000 8.766000 ;
      RECT 0.000000 8.190000 27.540000 8.514000 ;
      RECT 27.521000 7.938000 27.540000 8.190000 ;
      RECT 19.521000 7.938000 26.879000 8.190000 ;
      RECT 11.521000 7.938000 18.879000 8.190000 ;
      RECT 3.521000 7.938000 10.879000 8.190000 ;
      RECT 0.000000 7.938000 2.879000 8.190000 ;
      RECT 0.000000 7.614000 27.540000 7.938000 ;
      RECT 20.401000 7.362000 27.540000 7.614000 ;
      RECT 12.401000 7.362000 19.759000 7.614000 ;
      RECT 4.401000 7.362000 11.759000 7.614000 ;
      RECT 0.000000 7.362000 3.759000 7.614000 ;
      RECT 0.000000 7.038000 27.540000 7.362000 ;
      RECT 27.521000 6.786000 27.540000 7.038000 ;
      RECT 19.521000 6.786000 26.879000 7.038000 ;
      RECT 11.521000 6.786000 18.879000 7.038000 ;
      RECT 3.521000 6.786000 10.879000 7.038000 ;
      RECT 0.000000 6.786000 2.879000 7.038000 ;
      RECT 0.000000 6.462000 27.540000 6.786000 ;
      RECT 20.401000 6.210000 27.540000 6.462000 ;
      RECT 12.401000 6.210000 19.759000 6.462000 ;
      RECT 4.401000 6.210000 11.759000 6.462000 ;
      RECT 0.000000 6.210000 3.759000 6.462000 ;
      RECT 0.000000 5.886000 27.540000 6.210000 ;
      RECT 27.521000 5.634000 27.540000 5.886000 ;
      RECT 19.521000 5.634000 26.879000 5.886000 ;
      RECT 11.521000 5.634000 18.879000 5.886000 ;
      RECT 3.521000 5.634000 10.879000 5.886000 ;
      RECT 0.000000 5.634000 2.879000 5.886000 ;
      RECT 0.000000 5.310000 27.540000 5.634000 ;
      RECT 20.401000 5.058000 27.540000 5.310000 ;
      RECT 12.401000 5.058000 19.759000 5.310000 ;
      RECT 4.401000 5.058000 11.759000 5.310000 ;
      RECT 0.000000 5.058000 3.759000 5.310000 ;
      RECT 0.000000 4.734000 27.540000 5.058000 ;
      RECT 27.521000 4.482000 27.540000 4.734000 ;
      RECT 19.521000 4.482000 26.879000 4.734000 ;
      RECT 11.521000 4.482000 18.879000 4.734000 ;
      RECT 3.521000 4.482000 10.879000 4.734000 ;
      RECT 0.000000 4.482000 2.879000 4.734000 ;
      RECT 0.000000 4.158000 27.540000 4.482000 ;
      RECT 20.401000 3.906000 27.540000 4.158000 ;
      RECT 12.401000 3.906000 19.759000 4.158000 ;
      RECT 4.401000 3.906000 11.759000 4.158000 ;
      RECT 0.000000 3.906000 3.759000 4.158000 ;
      RECT 0.000000 3.582000 27.540000 3.906000 ;
      RECT 27.521000 3.330000 27.540000 3.582000 ;
      RECT 19.521000 3.330000 26.879000 3.582000 ;
      RECT 11.521000 3.330000 18.879000 3.582000 ;
      RECT 3.521000 3.330000 10.879000 3.582000 ;
      RECT 0.000000 3.330000 2.879000 3.582000 ;
      RECT 0.000000 3.006000 27.540000 3.330000 ;
      RECT 20.401000 2.754000 27.540000 3.006000 ;
      RECT 12.401000 2.754000 19.759000 3.006000 ;
      RECT 4.401000 2.754000 11.759000 3.006000 ;
      RECT 0.000000 2.754000 3.759000 3.006000 ;
      RECT 0.000000 2.430000 27.540000 2.754000 ;
      RECT 27.521000 2.178000 27.540000 2.430000 ;
      RECT 19.521000 2.178000 26.879000 2.430000 ;
      RECT 11.521000 2.178000 18.879000 2.430000 ;
      RECT 3.521000 2.178000 10.879000 2.430000 ;
      RECT 0.000000 2.178000 2.879000 2.430000 ;
      RECT 0.000000 1.854000 27.540000 2.178000 ;
      RECT 20.401000 1.602000 27.540000 1.854000 ;
      RECT 12.401000 1.602000 19.759000 1.854000 ;
      RECT 4.401000 1.602000 11.759000 1.854000 ;
      RECT 0.000000 1.602000 3.759000 1.854000 ;
      RECT 0.000000 1.278000 27.540000 1.602000 ;
      RECT 27.521000 1.026000 27.540000 1.278000 ;
      RECT 19.521000 1.026000 26.879000 1.278000 ;
      RECT 11.521000 1.026000 18.879000 1.278000 ;
      RECT 3.521000 1.026000 10.879000 1.278000 ;
      RECT 0.000000 1.026000 2.879000 1.278000 ;
      RECT 0.000000 0.702000 27.540000 1.026000 ;
      RECT 20.401000 0.450000 27.540000 0.702000 ;
      RECT 12.401000 0.450000 19.759000 0.702000 ;
      RECT 4.401000 0.450000 11.759000 0.702000 ;
      RECT 0.000000 0.450000 3.759000 0.702000 ;
      RECT 0.000000 0.077000 27.540000 0.450000 ;
      RECT 27.496000 0.000000 27.540000 0.077000 ;
      RECT 19.496000 0.000000 26.904000 0.077000 ;
      RECT 11.496000 0.000000 18.904000 0.077000 ;
      RECT 3.496000 0.000000 10.904000 0.077000 ;
      RECT 0.000000 0.000000 2.904000 0.077000 ;
    LAYER M3 ;
      RECT 20.464000 26.883000 27.540000 27.072000 ;
      RECT 12.464000 26.883000 19.696000 27.072000 ;
      RECT 4.464000 26.883000 11.696000 27.072000 ;
      RECT 0.000000 26.883000 3.696000 27.072000 ;
      RECT 0.000000 26.685000 27.540000 26.883000 ;
      RECT 19.584000 26.307000 26.816000 26.685000 ;
      RECT 11.584000 26.307000 18.816000 26.685000 ;
      RECT 3.584000 26.307000 10.816000 26.685000 ;
      RECT 0.000000 26.307000 2.816000 26.685000 ;
      RECT 0.000000 26.109000 27.540000 26.307000 ;
      RECT 20.464000 25.731000 27.540000 26.109000 ;
      RECT 12.464000 25.731000 19.696000 26.109000 ;
      RECT 4.464000 25.731000 11.696000 26.109000 ;
      RECT 0.000000 25.731000 3.696000 26.109000 ;
      RECT 0.000000 25.533000 27.540000 25.731000 ;
      RECT 19.584000 25.155000 26.816000 25.533000 ;
      RECT 11.584000 25.155000 18.816000 25.533000 ;
      RECT 3.584000 25.155000 10.816000 25.533000 ;
      RECT 0.000000 25.155000 2.816000 25.533000 ;
      RECT 0.000000 24.957000 27.540000 25.155000 ;
      RECT 20.464000 24.579000 27.540000 24.957000 ;
      RECT 12.464000 24.579000 19.696000 24.957000 ;
      RECT 4.464000 24.579000 11.696000 24.957000 ;
      RECT 0.000000 24.579000 3.696000 24.957000 ;
      RECT 0.000000 24.381000 27.540000 24.579000 ;
      RECT 19.584000 24.003000 26.816000 24.381000 ;
      RECT 11.584000 24.003000 18.816000 24.381000 ;
      RECT 3.584000 24.003000 10.816000 24.381000 ;
      RECT 0.000000 24.003000 2.816000 24.381000 ;
      RECT 0.000000 23.805000 27.540000 24.003000 ;
      RECT 20.464000 23.427000 27.540000 23.805000 ;
      RECT 12.464000 23.427000 19.696000 23.805000 ;
      RECT 4.464000 23.427000 11.696000 23.805000 ;
      RECT 0.000000 23.427000 3.696000 23.805000 ;
      RECT 0.000000 23.229000 27.540000 23.427000 ;
      RECT 19.584000 22.851000 26.816000 23.229000 ;
      RECT 11.584000 22.851000 18.816000 23.229000 ;
      RECT 3.584000 22.851000 10.816000 23.229000 ;
      RECT 0.000000 22.851000 2.816000 23.229000 ;
      RECT 0.000000 22.653000 27.540000 22.851000 ;
      RECT 20.464000 22.275000 27.540000 22.653000 ;
      RECT 12.464000 22.275000 19.696000 22.653000 ;
      RECT 4.464000 22.275000 11.696000 22.653000 ;
      RECT 0.000000 22.275000 3.696000 22.653000 ;
      RECT 0.000000 22.077000 27.540000 22.275000 ;
      RECT 19.584000 21.699000 26.816000 22.077000 ;
      RECT 11.584000 21.699000 18.816000 22.077000 ;
      RECT 3.584000 21.699000 10.816000 22.077000 ;
      RECT 0.000000 21.699000 2.816000 22.077000 ;
      RECT 0.000000 21.501000 27.540000 21.699000 ;
      RECT 20.464000 21.123000 27.540000 21.501000 ;
      RECT 12.464000 21.123000 19.696000 21.501000 ;
      RECT 4.464000 21.123000 11.696000 21.501000 ;
      RECT 0.000000 21.123000 3.696000 21.501000 ;
      RECT 0.000000 20.925000 27.540000 21.123000 ;
      RECT 19.584000 20.547000 26.816000 20.925000 ;
      RECT 11.584000 20.547000 18.816000 20.925000 ;
      RECT 3.584000 20.547000 10.816000 20.925000 ;
      RECT 0.000000 20.547000 2.816000 20.925000 ;
      RECT 0.000000 20.349000 27.540000 20.547000 ;
      RECT 20.464000 19.971000 27.540000 20.349000 ;
      RECT 12.464000 19.971000 19.696000 20.349000 ;
      RECT 4.464000 19.971000 11.696000 20.349000 ;
      RECT 0.000000 19.971000 3.696000 20.349000 ;
      RECT 0.000000 19.773000 27.540000 19.971000 ;
      RECT 19.584000 19.395000 26.816000 19.773000 ;
      RECT 11.584000 19.395000 18.816000 19.773000 ;
      RECT 3.584000 19.395000 10.816000 19.773000 ;
      RECT 0.000000 19.395000 2.816000 19.773000 ;
      RECT 0.000000 19.197000 27.540000 19.395000 ;
      RECT 20.464000 18.819000 27.540000 19.197000 ;
      RECT 12.464000 18.819000 19.696000 19.197000 ;
      RECT 4.464000 18.819000 11.696000 19.197000 ;
      RECT 0.000000 18.819000 3.696000 19.197000 ;
      RECT 0.000000 18.621000 27.540000 18.819000 ;
      RECT 19.584000 18.243000 26.816000 18.621000 ;
      RECT 11.584000 18.243000 18.816000 18.621000 ;
      RECT 3.584000 18.243000 10.816000 18.621000 ;
      RECT 0.000000 18.243000 2.816000 18.621000 ;
      RECT 0.000000 18.045000 27.540000 18.243000 ;
      RECT 20.464000 17.667000 27.540000 18.045000 ;
      RECT 12.464000 17.667000 19.696000 18.045000 ;
      RECT 4.464000 17.667000 11.696000 18.045000 ;
      RECT 0.000000 17.667000 3.696000 18.045000 ;
      RECT 0.000000 17.469000 27.540000 17.667000 ;
      RECT 19.584000 17.091000 26.816000 17.469000 ;
      RECT 11.584000 17.091000 18.816000 17.469000 ;
      RECT 3.584000 17.091000 10.816000 17.469000 ;
      RECT 0.000000 17.091000 2.816000 17.469000 ;
      RECT 0.000000 16.893000 27.540000 17.091000 ;
      RECT 20.464000 16.515000 27.540000 16.893000 ;
      RECT 12.464000 16.515000 19.696000 16.893000 ;
      RECT 4.464000 16.515000 11.696000 16.893000 ;
      RECT 0.000000 16.515000 3.696000 16.893000 ;
      RECT 0.000000 16.317000 27.540000 16.515000 ;
      RECT 19.584000 15.939000 26.816000 16.317000 ;
      RECT 11.584000 15.939000 18.816000 16.317000 ;
      RECT 3.584000 15.939000 10.816000 16.317000 ;
      RECT 0.000000 15.939000 2.816000 16.317000 ;
      RECT 0.000000 15.741000 27.540000 15.939000 ;
      RECT 20.464000 15.363000 27.540000 15.741000 ;
      RECT 12.464000 15.363000 19.696000 15.741000 ;
      RECT 4.464000 15.363000 11.696000 15.741000 ;
      RECT 0.000000 15.363000 3.696000 15.741000 ;
      RECT 0.000000 15.165000 27.540000 15.363000 ;
      RECT 19.584000 14.787000 26.816000 15.165000 ;
      RECT 11.584000 14.787000 18.816000 15.165000 ;
      RECT 3.584000 14.787000 10.816000 15.165000 ;
      RECT 0.000000 14.787000 2.816000 15.165000 ;
      RECT 0.000000 14.589000 27.540000 14.787000 ;
      RECT 20.464000 14.211000 27.540000 14.589000 ;
      RECT 12.464000 14.211000 19.696000 14.589000 ;
      RECT 4.464000 14.211000 11.696000 14.589000 ;
      RECT 0.000000 14.211000 3.696000 14.589000 ;
      RECT 0.000000 14.013000 27.540000 14.211000 ;
      RECT 19.584000 13.635000 26.816000 14.013000 ;
      RECT 11.584000 13.635000 18.816000 14.013000 ;
      RECT 3.584000 13.635000 10.816000 14.013000 ;
      RECT 0.000000 13.635000 2.816000 14.013000 ;
      RECT 0.000000 13.437000 27.540000 13.635000 ;
      RECT 20.464000 13.059000 27.540000 13.437000 ;
      RECT 12.464000 13.059000 19.696000 13.437000 ;
      RECT 4.464000 13.059000 11.696000 13.437000 ;
      RECT 0.000000 13.059000 3.696000 13.437000 ;
      RECT 0.000000 12.861000 27.540000 13.059000 ;
      RECT 19.584000 12.483000 26.816000 12.861000 ;
      RECT 11.584000 12.483000 18.816000 12.861000 ;
      RECT 3.584000 12.483000 10.816000 12.861000 ;
      RECT 0.000000 12.483000 2.816000 12.861000 ;
      RECT 0.000000 12.285000 27.540000 12.483000 ;
      RECT 20.464000 11.907000 27.540000 12.285000 ;
      RECT 12.464000 11.907000 19.696000 12.285000 ;
      RECT 4.464000 11.907000 11.696000 12.285000 ;
      RECT 0.000000 11.907000 3.696000 12.285000 ;
      RECT 0.000000 11.709000 27.540000 11.907000 ;
      RECT 19.584000 11.331000 26.816000 11.709000 ;
      RECT 11.584000 11.331000 18.816000 11.709000 ;
      RECT 3.584000 11.331000 10.816000 11.709000 ;
      RECT 0.000000 11.331000 2.816000 11.709000 ;
      RECT 0.000000 11.133000 27.540000 11.331000 ;
      RECT 20.464000 10.755000 27.540000 11.133000 ;
      RECT 12.464000 10.755000 19.696000 11.133000 ;
      RECT 4.464000 10.755000 11.696000 11.133000 ;
      RECT 0.000000 10.755000 3.696000 11.133000 ;
      RECT 0.000000 10.557000 27.540000 10.755000 ;
      RECT 19.584000 10.179000 26.816000 10.557000 ;
      RECT 11.584000 10.179000 18.816000 10.557000 ;
      RECT 3.584000 10.179000 10.816000 10.557000 ;
      RECT 0.000000 10.179000 2.816000 10.557000 ;
      RECT 0.000000 9.981000 27.540000 10.179000 ;
      RECT 20.464000 9.603000 27.540000 9.981000 ;
      RECT 12.464000 9.603000 19.696000 9.981000 ;
      RECT 4.464000 9.603000 11.696000 9.981000 ;
      RECT 0.000000 9.603000 3.696000 9.981000 ;
      RECT 0.000000 9.405000 27.540000 9.603000 ;
      RECT 19.584000 9.027000 26.816000 9.405000 ;
      RECT 11.584000 9.027000 18.816000 9.405000 ;
      RECT 3.584000 9.027000 10.816000 9.405000 ;
      RECT 0.000000 9.027000 2.816000 9.405000 ;
      RECT 0.000000 8.829000 27.540000 9.027000 ;
      RECT 20.464000 8.451000 27.540000 8.829000 ;
      RECT 12.464000 8.451000 19.696000 8.829000 ;
      RECT 4.464000 8.451000 11.696000 8.829000 ;
      RECT 0.000000 8.451000 3.696000 8.829000 ;
      RECT 0.000000 8.253000 27.540000 8.451000 ;
      RECT 19.584000 7.875000 26.816000 8.253000 ;
      RECT 11.584000 7.875000 18.816000 8.253000 ;
      RECT 3.584000 7.875000 10.816000 8.253000 ;
      RECT 0.000000 7.875000 2.816000 8.253000 ;
      RECT 0.000000 7.677000 27.540000 7.875000 ;
      RECT 20.464000 7.299000 27.540000 7.677000 ;
      RECT 12.464000 7.299000 19.696000 7.677000 ;
      RECT 4.464000 7.299000 11.696000 7.677000 ;
      RECT 0.000000 7.299000 3.696000 7.677000 ;
      RECT 0.000000 7.101000 27.540000 7.299000 ;
      RECT 19.584000 6.723000 26.816000 7.101000 ;
      RECT 11.584000 6.723000 18.816000 7.101000 ;
      RECT 3.584000 6.723000 10.816000 7.101000 ;
      RECT 0.000000 6.723000 2.816000 7.101000 ;
      RECT 0.000000 6.525000 27.540000 6.723000 ;
      RECT 20.464000 6.147000 27.540000 6.525000 ;
      RECT 12.464000 6.147000 19.696000 6.525000 ;
      RECT 4.464000 6.147000 11.696000 6.525000 ;
      RECT 0.000000 6.147000 3.696000 6.525000 ;
      RECT 0.000000 5.949000 27.540000 6.147000 ;
      RECT 19.584000 5.571000 26.816000 5.949000 ;
      RECT 11.584000 5.571000 18.816000 5.949000 ;
      RECT 3.584000 5.571000 10.816000 5.949000 ;
      RECT 0.000000 5.571000 2.816000 5.949000 ;
      RECT 0.000000 5.373000 27.540000 5.571000 ;
      RECT 20.464000 4.995000 27.540000 5.373000 ;
      RECT 12.464000 4.995000 19.696000 5.373000 ;
      RECT 4.464000 4.995000 11.696000 5.373000 ;
      RECT 0.000000 4.995000 3.696000 5.373000 ;
      RECT 0.000000 4.797000 27.540000 4.995000 ;
      RECT 19.584000 4.419000 26.816000 4.797000 ;
      RECT 11.584000 4.419000 18.816000 4.797000 ;
      RECT 3.584000 4.419000 10.816000 4.797000 ;
      RECT 0.000000 4.419000 2.816000 4.797000 ;
      RECT 0.000000 4.221000 27.540000 4.419000 ;
      RECT 20.464000 3.843000 27.540000 4.221000 ;
      RECT 12.464000 3.843000 19.696000 4.221000 ;
      RECT 4.464000 3.843000 11.696000 4.221000 ;
      RECT 0.000000 3.843000 3.696000 4.221000 ;
      RECT 0.000000 3.645000 27.540000 3.843000 ;
      RECT 19.584000 3.267000 26.816000 3.645000 ;
      RECT 11.584000 3.267000 18.816000 3.645000 ;
      RECT 3.584000 3.267000 10.816000 3.645000 ;
      RECT 0.000000 3.267000 2.816000 3.645000 ;
      RECT 0.000000 3.069000 27.540000 3.267000 ;
      RECT 20.464000 2.691000 27.540000 3.069000 ;
      RECT 12.464000 2.691000 19.696000 3.069000 ;
      RECT 4.464000 2.691000 11.696000 3.069000 ;
      RECT 0.000000 2.691000 3.696000 3.069000 ;
      RECT 0.000000 2.493000 27.540000 2.691000 ;
      RECT 19.584000 2.115000 26.816000 2.493000 ;
      RECT 11.584000 2.115000 18.816000 2.493000 ;
      RECT 3.584000 2.115000 10.816000 2.493000 ;
      RECT 0.000000 2.115000 2.816000 2.493000 ;
      RECT 0.000000 1.917000 27.540000 2.115000 ;
      RECT 20.464000 1.539000 27.540000 1.917000 ;
      RECT 12.464000 1.539000 19.696000 1.917000 ;
      RECT 4.464000 1.539000 11.696000 1.917000 ;
      RECT 0.000000 1.539000 3.696000 1.917000 ;
      RECT 0.000000 1.341000 27.540000 1.539000 ;
      RECT 19.584000 0.963000 26.816000 1.341000 ;
      RECT 11.584000 0.963000 18.816000 1.341000 ;
      RECT 3.584000 0.963000 10.816000 1.341000 ;
      RECT 0.000000 0.963000 2.816000 1.341000 ;
      RECT 0.000000 0.765000 27.540000 0.963000 ;
      RECT 20.464000 0.387000 27.540000 0.765000 ;
      RECT 12.464000 0.387000 19.696000 0.765000 ;
      RECT 4.464000 0.387000 11.696000 0.765000 ;
      RECT 0.000000 0.387000 3.696000 0.765000 ;
      RECT 0.000000 0.189000 27.540000 0.387000 ;
      RECT 19.584000 0.000000 26.816000 0.189000 ;
      RECT 11.584000 0.000000 18.816000 0.189000 ;
      RECT 3.584000 0.000000 10.816000 0.189000 ;
      RECT 0.000000 0.000000 2.816000 0.189000 ;
    LAYER M4 ;
      RECT 20.420000 26.930000 27.540000 27.072000 ;
      RECT 12.420000 26.930000 19.740000 27.072000 ;
      RECT 4.420000 26.930000 11.740000 27.072000 ;
      RECT 0.000000 26.930000 3.740000 27.072000 ;
      RECT 0.000000 26.621000 27.540000 26.930000 ;
      RECT 27.520000 26.371000 27.540000 26.621000 ;
      RECT 19.520000 26.371000 26.880000 26.621000 ;
      RECT 11.520000 26.371000 18.880000 26.621000 ;
      RECT 3.520000 26.371000 10.880000 26.621000 ;
      RECT 0.000000 26.371000 2.880000 26.621000 ;
      RECT 0.000000 26.300000 27.540000 26.371000 ;
      RECT 0.000000 26.220000 27.075000 26.300000 ;
      RECT 0.465000 26.180000 27.075000 26.220000 ;
      RECT 0.465000 26.100000 27.540000 26.180000 ;
      RECT 0.000000 26.045000 27.540000 26.100000 ;
      RECT 20.400000 25.795000 27.540000 26.045000 ;
      RECT 12.400000 25.795000 19.760000 26.045000 ;
      RECT 4.400000 25.795000 11.760000 26.045000 ;
      RECT 0.000000 25.795000 3.760000 26.045000 ;
      RECT 0.000000 25.580000 27.540000 25.795000 ;
      RECT 0.000000 25.500000 27.075000 25.580000 ;
      RECT 0.465000 25.469000 27.075000 25.500000 ;
      RECT 0.465000 25.380000 2.880000 25.469000 ;
      RECT 27.520000 25.219000 27.540000 25.460000 ;
      RECT 19.520000 25.219000 26.880000 25.469000 ;
      RECT 11.520000 25.219000 18.880000 25.469000 ;
      RECT 3.520000 25.219000 10.880000 25.469000 ;
      RECT 0.000000 25.219000 2.880000 25.380000 ;
      RECT 0.000000 24.893000 27.540000 25.219000 ;
      RECT 20.400000 24.700000 27.540000 24.893000 ;
      RECT 0.000000 24.700000 3.760000 24.893000 ;
      RECT 20.400000 24.643000 27.075000 24.700000 ;
      RECT 12.400000 24.643000 19.760000 24.893000 ;
      RECT 4.400000 24.643000 11.760000 24.893000 ;
      RECT 0.465000 24.643000 3.760000 24.700000 ;
      RECT 0.465000 24.580000 27.075000 24.643000 ;
      RECT 0.000000 24.317000 27.540000 24.580000 ;
      RECT 27.520000 24.067000 27.540000 24.317000 ;
      RECT 19.520000 24.067000 26.880000 24.317000 ;
      RECT 11.520000 24.067000 18.880000 24.317000 ;
      RECT 3.520000 24.067000 10.880000 24.317000 ;
      RECT 0.000000 24.067000 2.880000 24.317000 ;
      RECT 0.000000 23.980000 27.540000 24.067000 ;
      RECT 0.465000 23.900000 27.540000 23.980000 ;
      RECT 0.465000 23.860000 27.075000 23.900000 ;
      RECT 0.000000 23.780000 27.075000 23.860000 ;
      RECT 0.000000 23.741000 27.540000 23.780000 ;
      RECT 20.400000 23.491000 27.540000 23.741000 ;
      RECT 12.400000 23.491000 19.760000 23.741000 ;
      RECT 4.400000 23.491000 11.760000 23.741000 ;
      RECT 0.000000 23.491000 3.760000 23.741000 ;
      RECT 0.000000 23.260000 27.540000 23.491000 ;
      RECT 0.000000 23.180000 27.075000 23.260000 ;
      RECT 0.465000 23.165000 27.075000 23.180000 ;
      RECT 0.465000 23.060000 2.880000 23.165000 ;
      RECT 27.520000 22.915000 27.540000 23.140000 ;
      RECT 19.520000 22.915000 26.880000 23.165000 ;
      RECT 11.520000 22.915000 18.880000 23.165000 ;
      RECT 3.520000 22.915000 10.880000 23.165000 ;
      RECT 0.000000 22.915000 2.880000 23.060000 ;
      RECT 0.000000 22.589000 27.540000 22.915000 ;
      RECT 0.000000 22.380000 3.760000 22.589000 ;
      RECT 20.400000 22.339000 27.540000 22.589000 ;
      RECT 12.400000 22.339000 19.760000 22.589000 ;
      RECT 4.400000 22.339000 11.760000 22.589000 ;
      RECT 0.465000 22.339000 3.760000 22.380000 ;
      RECT 0.465000 22.260000 27.540000 22.339000 ;
      RECT 0.000000 22.220000 27.540000 22.260000 ;
      RECT 0.000000 22.100000 27.075000 22.220000 ;
      RECT 0.000000 22.013000 27.540000 22.100000 ;
      RECT 27.520000 21.763000 27.540000 22.013000 ;
      RECT 19.520000 21.763000 26.880000 22.013000 ;
      RECT 11.520000 21.763000 18.880000 22.013000 ;
      RECT 3.520000 21.763000 10.880000 22.013000 ;
      RECT 0.000000 21.763000 2.880000 22.013000 ;
      RECT 0.000000 21.660000 27.540000 21.763000 ;
      RECT 0.465000 21.540000 27.540000 21.660000 ;
      RECT 0.000000 21.437000 27.540000 21.540000 ;
      RECT 20.400000 21.420000 27.540000 21.437000 ;
      RECT 20.400000 21.300000 27.075000 21.420000 ;
      RECT 20.400000 21.187000 27.540000 21.300000 ;
      RECT 12.400000 21.187000 19.760000 21.437000 ;
      RECT 4.400000 21.187000 11.760000 21.437000 ;
      RECT 0.000000 21.187000 3.760000 21.437000 ;
      RECT 0.000000 20.861000 27.540000 21.187000 ;
      RECT 0.000000 20.860000 2.880000 20.861000 ;
      RECT 0.465000 20.740000 2.880000 20.860000 ;
      RECT 27.520000 20.620000 27.540000 20.861000 ;
      RECT 19.520000 20.611000 26.880000 20.861000 ;
      RECT 11.520000 20.611000 18.880000 20.861000 ;
      RECT 3.520000 20.611000 10.880000 20.861000 ;
      RECT 0.000000 20.611000 2.880000 20.740000 ;
      RECT 0.000000 20.500000 27.075000 20.611000 ;
      RECT 0.000000 20.285000 27.540000 20.500000 ;
      RECT 0.000000 20.060000 3.760000 20.285000 ;
      RECT 20.400000 20.035000 27.540000 20.285000 ;
      RECT 12.400000 20.035000 19.760000 20.285000 ;
      RECT 4.400000 20.035000 11.760000 20.285000 ;
      RECT 0.465000 20.035000 3.760000 20.060000 ;
      RECT 0.465000 19.940000 27.540000 20.035000 ;
      RECT 0.000000 19.820000 27.540000 19.940000 ;
      RECT 0.000000 19.709000 27.075000 19.820000 ;
      RECT 27.520000 19.459000 27.540000 19.700000 ;
      RECT 19.520000 19.459000 26.880000 19.709000 ;
      RECT 11.520000 19.459000 18.880000 19.709000 ;
      RECT 3.520000 19.459000 10.880000 19.709000 ;
      RECT 0.000000 19.459000 2.880000 19.709000 ;
      RECT 0.000000 19.340000 27.540000 19.459000 ;
      RECT 0.465000 19.220000 27.540000 19.340000 ;
      RECT 0.000000 19.133000 27.540000 19.220000 ;
      RECT 20.400000 18.940000 27.540000 19.133000 ;
      RECT 20.400000 18.883000 27.075000 18.940000 ;
      RECT 12.400000 18.883000 19.760000 19.133000 ;
      RECT 4.400000 18.883000 11.760000 19.133000 ;
      RECT 0.000000 18.883000 3.760000 19.133000 ;
      RECT 0.000000 18.820000 27.075000 18.883000 ;
      RECT 0.000000 18.557000 27.540000 18.820000 ;
      RECT 0.000000 18.540000 2.880000 18.557000 ;
      RECT 0.465000 18.420000 2.880000 18.540000 ;
      RECT 27.520000 18.307000 27.540000 18.557000 ;
      RECT 19.520000 18.307000 26.880000 18.557000 ;
      RECT 11.520000 18.307000 18.880000 18.557000 ;
      RECT 3.520000 18.307000 10.880000 18.557000 ;
      RECT 0.000000 18.307000 2.880000 18.420000 ;
      RECT 0.000000 18.140000 27.540000 18.307000 ;
      RECT 0.000000 18.020000 27.075000 18.140000 ;
      RECT 0.000000 17.981000 27.540000 18.020000 ;
      RECT 0.000000 17.740000 3.760000 17.981000 ;
      RECT 20.400000 17.731000 27.540000 17.981000 ;
      RECT 12.400000 17.731000 19.760000 17.981000 ;
      RECT 4.400000 17.731000 11.760000 17.981000 ;
      RECT 0.465000 17.731000 3.760000 17.740000 ;
      RECT 0.465000 17.620000 27.540000 17.731000 ;
      RECT 0.000000 17.500000 27.540000 17.620000 ;
      RECT 0.000000 17.405000 27.075000 17.500000 ;
      RECT 27.520000 17.155000 27.540000 17.380000 ;
      RECT 19.520000 17.155000 26.880000 17.405000 ;
      RECT 11.520000 17.155000 18.880000 17.405000 ;
      RECT 3.520000 17.155000 10.880000 17.405000 ;
      RECT 0.000000 17.155000 2.880000 17.405000 ;
      RECT 0.000000 17.020000 27.540000 17.155000 ;
      RECT 0.465000 16.900000 27.540000 17.020000 ;
      RECT 0.000000 16.829000 27.540000 16.900000 ;
      RECT 20.400000 16.579000 27.540000 16.829000 ;
      RECT 12.400000 16.579000 19.760000 16.829000 ;
      RECT 4.400000 16.579000 11.760000 16.829000 ;
      RECT 0.000000 16.579000 3.760000 16.829000 ;
      RECT 0.000000 16.540000 27.540000 16.579000 ;
      RECT 0.000000 16.420000 27.075000 16.540000 ;
      RECT 0.000000 16.253000 27.540000 16.420000 ;
      RECT 0.000000 16.220000 2.880000 16.253000 ;
      RECT 0.465000 16.100000 2.880000 16.220000 ;
      RECT 27.520000 16.003000 27.540000 16.253000 ;
      RECT 19.520000 16.003000 26.880000 16.253000 ;
      RECT 11.520000 16.003000 18.880000 16.253000 ;
      RECT 3.520000 16.003000 10.880000 16.253000 ;
      RECT 0.000000 16.003000 2.880000 16.100000 ;
      RECT 0.000000 15.740000 27.540000 16.003000 ;
      RECT 0.000000 15.677000 27.075000 15.740000 ;
      RECT 20.400000 15.620000 27.075000 15.677000 ;
      RECT 0.000000 15.500000 3.760000 15.677000 ;
      RECT 20.400000 15.427000 27.540000 15.620000 ;
      RECT 12.400000 15.427000 19.760000 15.677000 ;
      RECT 4.400000 15.427000 11.760000 15.677000 ;
      RECT 0.465000 15.427000 3.760000 15.500000 ;
      RECT 0.465000 15.380000 27.540000 15.427000 ;
      RECT 0.000000 15.101000 27.540000 15.380000 ;
      RECT 27.520000 14.860000 27.540000 15.101000 ;
      RECT 19.520000 14.851000 26.880000 15.101000 ;
      RECT 11.520000 14.851000 18.880000 15.101000 ;
      RECT 3.520000 14.851000 10.880000 15.101000 ;
      RECT 0.000000 14.851000 2.880000 15.101000 ;
      RECT 0.000000 14.740000 27.075000 14.851000 ;
      RECT 0.000000 14.700000 27.540000 14.740000 ;
      RECT 0.465000 14.580000 27.540000 14.700000 ;
      RECT 0.000000 14.525000 27.540000 14.580000 ;
      RECT 20.400000 14.275000 27.540000 14.525000 ;
      RECT 12.400000 14.275000 19.760000 14.525000 ;
      RECT 4.400000 14.275000 11.760000 14.525000 ;
      RECT 0.000000 14.275000 3.760000 14.525000 ;
      RECT 0.000000 14.060000 27.540000 14.275000 ;
      RECT 0.000000 13.949000 27.075000 14.060000 ;
      RECT 0.000000 13.900000 2.880000 13.949000 ;
      RECT 0.465000 13.780000 2.880000 13.900000 ;
      RECT 27.520000 13.699000 27.540000 13.940000 ;
      RECT 19.520000 13.699000 26.880000 13.949000 ;
      RECT 11.520000 13.699000 18.880000 13.949000 ;
      RECT 3.520000 13.699000 10.880000 13.949000 ;
      RECT 0.000000 13.699000 2.880000 13.780000 ;
      RECT 0.000000 13.373000 27.540000 13.699000 ;
      RECT 20.400000 13.260000 27.540000 13.373000 ;
      RECT 0.000000 13.180000 3.760000 13.373000 ;
      RECT 20.400000 13.140000 27.075000 13.260000 ;
      RECT 20.400000 13.123000 27.540000 13.140000 ;
      RECT 12.400000 13.123000 19.760000 13.373000 ;
      RECT 4.400000 13.123000 11.760000 13.373000 ;
      RECT 0.465000 13.123000 3.760000 13.180000 ;
      RECT 0.465000 13.060000 27.540000 13.123000 ;
      RECT 0.000000 12.797000 27.540000 13.060000 ;
      RECT 27.520000 12.547000 27.540000 12.797000 ;
      RECT 19.520000 12.547000 26.880000 12.797000 ;
      RECT 11.520000 12.547000 18.880000 12.797000 ;
      RECT 3.520000 12.547000 10.880000 12.797000 ;
      RECT 0.000000 12.547000 2.880000 12.797000 ;
      RECT 0.000000 12.460000 27.540000 12.547000 ;
      RECT 0.000000 12.380000 27.075000 12.460000 ;
      RECT 0.465000 12.340000 27.075000 12.380000 ;
      RECT 0.465000 12.260000 27.540000 12.340000 ;
      RECT 0.000000 12.221000 27.540000 12.260000 ;
      RECT 20.400000 11.971000 27.540000 12.221000 ;
      RECT 12.400000 11.971000 19.760000 12.221000 ;
      RECT 4.400000 11.971000 11.760000 12.221000 ;
      RECT 0.000000 11.971000 3.760000 12.221000 ;
      RECT 0.000000 11.740000 27.540000 11.971000 ;
      RECT 0.000000 11.645000 27.075000 11.740000 ;
      RECT 0.000000 11.580000 2.880000 11.645000 ;
      RECT 0.465000 11.460000 2.880000 11.580000 ;
      RECT 27.520000 11.395000 27.540000 11.620000 ;
      RECT 19.520000 11.395000 26.880000 11.645000 ;
      RECT 11.520000 11.395000 18.880000 11.645000 ;
      RECT 3.520000 11.395000 10.880000 11.645000 ;
      RECT 0.000000 11.395000 2.880000 11.460000 ;
      RECT 0.000000 11.069000 27.540000 11.395000 ;
      RECT 0.000000 10.860000 3.760000 11.069000 ;
      RECT 20.400000 10.819000 27.540000 11.069000 ;
      RECT 12.400000 10.819000 19.760000 11.069000 ;
      RECT 4.400000 10.819000 11.760000 11.069000 ;
      RECT 0.465000 10.819000 3.760000 10.860000 ;
      RECT 0.465000 10.780000 27.540000 10.819000 ;
      RECT 0.465000 10.740000 27.075000 10.780000 ;
      RECT 0.000000 10.660000 27.075000 10.740000 ;
      RECT 0.000000 10.493000 27.540000 10.660000 ;
      RECT 27.520000 10.243000 27.540000 10.493000 ;
      RECT 19.520000 10.243000 26.880000 10.493000 ;
      RECT 11.520000 10.243000 18.880000 10.493000 ;
      RECT 3.520000 10.243000 10.880000 10.493000 ;
      RECT 0.000000 10.243000 2.880000 10.493000 ;
      RECT 0.000000 10.060000 27.540000 10.243000 ;
      RECT 0.465000 9.980000 27.540000 10.060000 ;
      RECT 0.465000 9.940000 27.075000 9.980000 ;
      RECT 0.000000 9.917000 27.075000 9.940000 ;
      RECT 20.400000 9.860000 27.075000 9.917000 ;
      RECT 20.400000 9.667000 27.540000 9.860000 ;
      RECT 12.400000 9.667000 19.760000 9.917000 ;
      RECT 4.400000 9.667000 11.760000 9.917000 ;
      RECT 0.000000 9.667000 3.760000 9.917000 ;
      RECT 0.000000 9.341000 27.540000 9.667000 ;
      RECT 0.000000 9.340000 2.880000 9.341000 ;
      RECT 0.465000 9.220000 2.880000 9.340000 ;
      RECT 27.520000 9.100000 27.540000 9.341000 ;
      RECT 19.520000 9.091000 26.880000 9.341000 ;
      RECT 11.520000 9.091000 18.880000 9.341000 ;
      RECT 3.520000 9.091000 10.880000 9.341000 ;
      RECT 0.000000 9.091000 2.880000 9.220000 ;
      RECT 0.000000 8.980000 27.075000 9.091000 ;
      RECT 0.000000 8.765000 27.540000 8.980000 ;
      RECT 0.000000 8.540000 3.760000 8.765000 ;
      RECT 20.400000 8.515000 27.540000 8.765000 ;
      RECT 12.400000 8.515000 19.760000 8.765000 ;
      RECT 4.400000 8.515000 11.760000 8.765000 ;
      RECT 0.465000 8.515000 3.760000 8.540000 ;
      RECT 0.465000 8.420000 27.540000 8.515000 ;
      RECT 0.000000 8.380000 27.540000 8.420000 ;
      RECT 0.000000 8.260000 27.075000 8.380000 ;
      RECT 0.000000 8.189000 27.540000 8.260000 ;
      RECT 27.520000 7.939000 27.540000 8.189000 ;
      RECT 19.520000 7.939000 26.880000 8.189000 ;
      RECT 11.520000 7.939000 18.880000 8.189000 ;
      RECT 3.520000 7.939000 10.880000 8.189000 ;
      RECT 0.000000 7.939000 2.880000 8.189000 ;
      RECT 0.000000 7.740000 27.540000 7.939000 ;
      RECT 0.465000 7.620000 27.540000 7.740000 ;
      RECT 0.000000 7.613000 27.540000 7.620000 ;
      RECT 20.400000 7.500000 27.540000 7.613000 ;
      RECT 20.400000 7.380000 27.075000 7.500000 ;
      RECT 20.400000 7.363000 27.540000 7.380000 ;
      RECT 12.400000 7.363000 19.760000 7.613000 ;
      RECT 4.400000 7.363000 11.760000 7.613000 ;
      RECT 0.000000 7.363000 3.760000 7.613000 ;
      RECT 0.000000 7.037000 27.540000 7.363000 ;
      RECT 0.000000 7.020000 2.880000 7.037000 ;
      RECT 0.465000 6.900000 2.880000 7.020000 ;
      RECT 27.520000 6.787000 27.540000 7.037000 ;
      RECT 19.520000 6.787000 26.880000 7.037000 ;
      RECT 11.520000 6.787000 18.880000 7.037000 ;
      RECT 3.520000 6.787000 10.880000 7.037000 ;
      RECT 0.000000 6.787000 2.880000 6.900000 ;
      RECT 0.000000 6.700000 27.540000 6.787000 ;
      RECT 0.000000 6.580000 27.075000 6.700000 ;
      RECT 0.000000 6.461000 27.540000 6.580000 ;
      RECT 0.000000 6.220000 3.760000 6.461000 ;
      RECT 20.400000 6.211000 27.540000 6.461000 ;
      RECT 12.400000 6.211000 19.760000 6.461000 ;
      RECT 4.400000 6.211000 11.760000 6.461000 ;
      RECT 0.465000 6.211000 3.760000 6.220000 ;
      RECT 0.465000 6.100000 27.540000 6.211000 ;
      RECT 0.000000 5.980000 27.540000 6.100000 ;
      RECT 0.000000 5.885000 27.075000 5.980000 ;
      RECT 27.520000 5.635000 27.540000 5.860000 ;
      RECT 19.520000 5.635000 26.880000 5.885000 ;
      RECT 11.520000 5.635000 18.880000 5.885000 ;
      RECT 3.520000 5.635000 10.880000 5.885000 ;
      RECT 0.000000 5.635000 2.880000 5.885000 ;
      RECT 0.000000 5.420000 27.540000 5.635000 ;
      RECT 0.465000 5.309000 27.540000 5.420000 ;
      RECT 0.465000 5.300000 3.760000 5.309000 ;
      RECT 20.400000 5.100000 27.540000 5.309000 ;
      RECT 20.400000 5.059000 27.075000 5.100000 ;
      RECT 12.400000 5.059000 19.760000 5.309000 ;
      RECT 4.400000 5.059000 11.760000 5.309000 ;
      RECT 0.000000 5.059000 3.760000 5.300000 ;
      RECT 0.000000 4.980000 27.075000 5.059000 ;
      RECT 0.000000 4.733000 27.540000 4.980000 ;
      RECT 0.000000 4.700000 2.880000 4.733000 ;
      RECT 0.465000 4.580000 2.880000 4.700000 ;
      RECT 27.520000 4.483000 27.540000 4.733000 ;
      RECT 19.520000 4.483000 26.880000 4.733000 ;
      RECT 11.520000 4.483000 18.880000 4.733000 ;
      RECT 3.520000 4.483000 10.880000 4.733000 ;
      RECT 0.000000 4.483000 2.880000 4.580000 ;
      RECT 0.000000 4.220000 27.540000 4.483000 ;
      RECT 0.000000 4.157000 27.075000 4.220000 ;
      RECT 20.400000 4.100000 27.075000 4.157000 ;
      RECT 20.400000 3.907000 27.540000 4.100000 ;
      RECT 12.400000 3.907000 19.760000 4.157000 ;
      RECT 4.400000 3.907000 11.760000 4.157000 ;
      RECT 0.000000 3.907000 3.760000 4.157000 ;
      RECT 0.000000 3.900000 27.540000 3.907000 ;
      RECT 0.465000 3.780000 27.540000 3.900000 ;
      RECT 0.000000 3.581000 27.540000 3.780000 ;
      RECT 27.520000 3.340000 27.540000 3.581000 ;
      RECT 19.520000 3.331000 26.880000 3.581000 ;
      RECT 11.520000 3.331000 18.880000 3.581000 ;
      RECT 3.520000 3.331000 10.880000 3.581000 ;
      RECT 0.000000 3.331000 2.880000 3.581000 ;
      RECT 0.000000 3.220000 27.075000 3.331000 ;
      RECT 0.000000 3.100000 27.540000 3.220000 ;
      RECT 0.465000 3.005000 27.540000 3.100000 ;
      RECT 0.465000 2.980000 3.760000 3.005000 ;
      RECT 20.400000 2.755000 27.540000 3.005000 ;
      RECT 12.400000 2.755000 19.760000 3.005000 ;
      RECT 4.400000 2.755000 11.760000 3.005000 ;
      RECT 0.000000 2.755000 3.760000 2.980000 ;
      RECT 0.000000 2.620000 27.540000 2.755000 ;
      RECT 0.000000 2.500000 27.075000 2.620000 ;
      RECT 0.000000 2.429000 27.540000 2.500000 ;
      RECT 0.000000 2.380000 2.880000 2.429000 ;
      RECT 0.465000 2.260000 2.880000 2.380000 ;
      RECT 27.520000 2.179000 27.540000 2.429000 ;
      RECT 19.520000 2.179000 26.880000 2.429000 ;
      RECT 11.520000 2.179000 18.880000 2.429000 ;
      RECT 3.520000 2.179000 10.880000 2.429000 ;
      RECT 0.000000 2.179000 2.880000 2.260000 ;
      RECT 0.000000 1.853000 27.540000 2.179000 ;
      RECT 20.400000 1.820000 27.540000 1.853000 ;
      RECT 20.400000 1.700000 27.075000 1.820000 ;
      RECT 20.400000 1.603000 27.540000 1.700000 ;
      RECT 12.400000 1.603000 19.760000 1.853000 ;
      RECT 4.400000 1.603000 11.760000 1.853000 ;
      RECT 0.000000 1.603000 3.760000 1.853000 ;
      RECT 0.000000 1.580000 27.540000 1.603000 ;
      RECT 0.465000 1.460000 27.540000 1.580000 ;
      RECT 0.000000 1.277000 27.540000 1.460000 ;
      RECT 27.520000 1.027000 27.540000 1.277000 ;
      RECT 19.520000 1.027000 26.880000 1.277000 ;
      RECT 11.520000 1.027000 18.880000 1.277000 ;
      RECT 3.520000 1.027000 10.880000 1.277000 ;
      RECT 0.000000 1.027000 2.880000 1.277000 ;
      RECT 0.000000 0.940000 27.540000 1.027000 ;
      RECT 0.000000 0.860000 27.075000 0.940000 ;
      RECT 0.465000 0.820000 27.075000 0.860000 ;
      RECT 0.465000 0.740000 27.540000 0.820000 ;
      RECT 0.000000 0.701000 27.540000 0.740000 ;
      RECT 20.400000 0.451000 27.540000 0.701000 ;
      RECT 12.400000 0.451000 19.760000 0.701000 ;
      RECT 4.400000 0.451000 11.760000 0.701000 ;
      RECT 0.000000 0.451000 3.760000 0.701000 ;
      RECT 0.000000 0.143000 27.540000 0.451000 ;
      RECT 19.540000 0.000000 26.860000 0.143000 ;
      RECT 11.540000 0.000000 18.860000 0.143000 ;
      RECT 3.540000 0.000000 10.860000 0.143000 ;
      RECT 0.000000 0.000000 2.860000 0.143000 ;
    LAYER M5 ;
      RECT 20.520000 0.000000 26.760000 27.072000 ;
      RECT 12.520000 0.000000 18.760000 27.072000 ;
      RECT 4.520000 0.000000 10.760000 27.072000 ;
      RECT 0.000000 0.000000 2.760000 27.072000 ;
    LAYER M6 ;
      RECT 0.000000 0.000000 27.540000 27.072000 ;
    LAYER M7 ;
      RECT 0.000000 0.000000 27.540000 27.072000 ;
  END
END mult

END LIBRARY
